VERSION 5.8 ;
BUSBITCHARS "[]" ;
DIVIDERCHAR "/" ;
UNITS
    DATABASE MICRONS 1000 ;
END UNITS

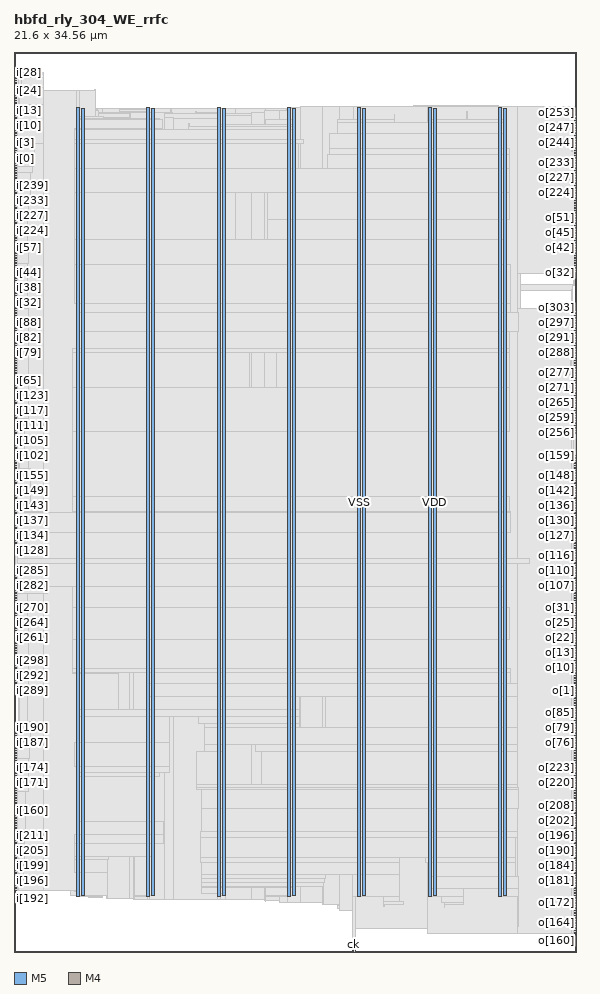
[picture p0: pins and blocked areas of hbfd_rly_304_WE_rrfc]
MACRO hbfd_rly_304_WE_rrfc
  FOREIGN hbfd_rly_304_WE_rrfc 0 0 ;
  CLASS BLOCK ;
  SIZE 21.6 BY 34.56 ;
  PIN ck
    DIRECTION INPUT ;
    USE SIGNAL ;
    PORT
      LAYER M5 ;
        RECT  13.008 0 13.032 0.084 ;
    END
  END ck
  PIN i[0]
    DIRECTION INPUT ;
    USE SIGNAL ;
    PORT
      LAYER M4 ;
        RECT  0 30.768 0.084 30.792 ;
    END
  END i[0]
  PIN i[100]
    DIRECTION INPUT ;
    USE SIGNAL ;
    PORT
      LAYER M4 ;
        RECT  0 18.864 0.084 18.888 ;
    END
  END i[100]
  PIN i[101]
    DIRECTION INPUT ;
    USE SIGNAL ;
    PORT
      LAYER M4 ;
        RECT  0 18.96 0.084 18.984 ;
    END
  END i[101]
  PIN i[102]
    DIRECTION INPUT ;
    USE SIGNAL ;
    PORT
      LAYER M4 ;
        RECT  0 19.056 0.084 19.08 ;
    END
  END i[102]
  PIN i[103]
    DIRECTION INPUT ;
    USE SIGNAL ;
    PORT
      LAYER M4 ;
        RECT  0 19.152 0.084 19.176 ;
    END
  END i[103]
  PIN i[104]
    DIRECTION INPUT ;
    USE SIGNAL ;
    PORT
      LAYER M4 ;
        RECT  0 19.248 0.084 19.272 ;
    END
  END i[104]
  PIN i[105]
    DIRECTION INPUT ;
    USE SIGNAL ;
    PORT
      LAYER M4 ;
        RECT  0 19.344 0.084 19.368 ;
    END
  END i[105]
  PIN i[106]
    DIRECTION INPUT ;
    USE SIGNAL ;
    PORT
      LAYER M4 ;
        RECT  0 19.44 0.084 19.464 ;
    END
  END i[106]
  PIN i[107]
    DIRECTION INPUT ;
    USE SIGNAL ;
    PORT
      LAYER M4 ;
        RECT  0 19.536 0.084 19.56 ;
    END
  END i[107]
  PIN i[108]
    DIRECTION INPUT ;
    USE SIGNAL ;
    PORT
      LAYER M4 ;
        RECT  0 19.632 0.084 19.656 ;
    END
  END i[108]
  PIN i[109]
    DIRECTION INPUT ;
    USE SIGNAL ;
    PORT
      LAYER M4 ;
        RECT  0 19.728 0.084 19.752 ;
    END
  END i[109]
  PIN i[10]
    DIRECTION INPUT ;
    USE SIGNAL ;
    PORT
      LAYER M4 ;
        RECT  0 31.728 0.084 31.752 ;
    END
  END i[10]
  PIN i[110]
    DIRECTION INPUT ;
    USE SIGNAL ;
    PORT
      LAYER M4 ;
        RECT  0 19.824 0.084 19.848 ;
    END
  END i[110]
  PIN i[111]
    DIRECTION INPUT ;
    USE SIGNAL ;
    PORT
      LAYER M4 ;
        RECT  0 19.92 0.084 19.944 ;
    END
  END i[111]
  PIN i[112]
    DIRECTION INPUT ;
    USE SIGNAL ;
    PORT
      LAYER M4 ;
        RECT  0 20.016 0.084 20.04 ;
    END
  END i[112]
  PIN i[113]
    DIRECTION INPUT ;
    USE SIGNAL ;
    PORT
      LAYER M4 ;
        RECT  0 20.112 0.084 20.136 ;
    END
  END i[113]
  PIN i[114]
    DIRECTION INPUT ;
    USE SIGNAL ;
    PORT
      LAYER M4 ;
        RECT  0 20.208 0.084 20.232 ;
    END
  END i[114]
  PIN i[115]
    DIRECTION INPUT ;
    USE SIGNAL ;
    PORT
      LAYER M4 ;
        RECT  0 20.304 0.084 20.328 ;
    END
  END i[115]
  PIN i[116]
    DIRECTION INPUT ;
    USE SIGNAL ;
    PORT
      LAYER M4 ;
        RECT  0 20.4 0.084 20.424 ;
    END
  END i[116]
  PIN i[117]
    DIRECTION INPUT ;
    USE SIGNAL ;
    PORT
      LAYER M4 ;
        RECT  0 20.496 0.084 20.52 ;
    END
  END i[117]
  PIN i[118]
    DIRECTION INPUT ;
    USE SIGNAL ;
    PORT
      LAYER M4 ;
        RECT  0 20.592 0.084 20.616 ;
    END
  END i[118]
  PIN i[119]
    DIRECTION INPUT ;
    USE SIGNAL ;
    PORT
      LAYER M4 ;
        RECT  0 20.688 0.084 20.712 ;
    END
  END i[119]
  PIN i[11]
    DIRECTION INPUT ;
    USE SIGNAL ;
    PORT
      LAYER M4 ;
        RECT  0 31.824 0.084 31.848 ;
    END
  END i[11]
  PIN i[120]
    DIRECTION INPUT ;
    USE SIGNAL ;
    PORT
      LAYER M4 ;
        RECT  0 20.784 0.084 20.808 ;
    END
  END i[120]
  PIN i[121]
    DIRECTION INPUT ;
    USE SIGNAL ;
    PORT
      LAYER M4 ;
        RECT  0 20.88 0.084 20.904 ;
    END
  END i[121]
  PIN i[122]
    DIRECTION INPUT ;
    USE SIGNAL ;
    PORT
      LAYER M4 ;
        RECT  0 20.976 0.084 21 ;
    END
  END i[122]
  PIN i[123]
    DIRECTION INPUT ;
    USE SIGNAL ;
    PORT
      LAYER M4 ;
        RECT  0 21.072 0.084 21.096 ;
    END
  END i[123]
  PIN i[124]
    DIRECTION INPUT ;
    USE SIGNAL ;
    PORT
      LAYER M4 ;
        RECT  0 21.168 0.084 21.192 ;
    END
  END i[124]
  PIN i[125]
    DIRECTION INPUT ;
    USE SIGNAL ;
    PORT
      LAYER M4 ;
        RECT  0 21.264 0.084 21.288 ;
    END
  END i[125]
  PIN i[126]
    DIRECTION INPUT ;
    USE SIGNAL ;
    PORT
      LAYER M4 ;
        RECT  0 21.36 0.084 21.384 ;
    END
  END i[126]
  PIN i[127]
    DIRECTION INPUT ;
    USE SIGNAL ;
    PORT
      LAYER M4 ;
        RECT  0 21.456 0.084 21.48 ;
    END
  END i[127]
  PIN i[128]
    DIRECTION INPUT ;
    USE SIGNAL ;
    PORT
      LAYER M4 ;
        RECT  0 15.408 0.084 15.432 ;
    END
  END i[128]
  PIN i[129]
    DIRECTION INPUT ;
    USE SIGNAL ;
    PORT
      LAYER M4 ;
        RECT  0 15.504 0.084 15.528 ;
    END
  END i[129]
  PIN i[12]
    DIRECTION INPUT ;
    USE SIGNAL ;
    PORT
      LAYER M4 ;
        RECT  0 31.92 0.084 31.944 ;
    END
  END i[12]
  PIN i[130]
    DIRECTION INPUT ;
    USE SIGNAL ;
    PORT
      LAYER M4 ;
        RECT  0 15.6 0.084 15.624 ;
    END
  END i[130]
  PIN i[131]
    DIRECTION INPUT ;
    USE SIGNAL ;
    PORT
      LAYER M4 ;
        RECT  0 15.696 0.084 15.72 ;
    END
  END i[131]
  PIN i[132]
    DIRECTION INPUT ;
    USE SIGNAL ;
    PORT
      LAYER M4 ;
        RECT  0 15.792 0.084 15.816 ;
    END
  END i[132]
  PIN i[133]
    DIRECTION INPUT ;
    USE SIGNAL ;
    PORT
      LAYER M4 ;
        RECT  0 15.888 0.084 15.912 ;
    END
  END i[133]
  PIN i[134]
    DIRECTION INPUT ;
    USE SIGNAL ;
    PORT
      LAYER M4 ;
        RECT  0 15.984 0.084 16.008 ;
    END
  END i[134]
  PIN i[135]
    DIRECTION INPUT ;
    USE SIGNAL ;
    PORT
      LAYER M4 ;
        RECT  0 16.08 0.084 16.104 ;
    END
  END i[135]
  PIN i[136]
    DIRECTION INPUT ;
    USE SIGNAL ;
    PORT
      LAYER M4 ;
        RECT  0 16.176 0.084 16.2 ;
    END
  END i[136]
  PIN i[137]
    DIRECTION INPUT ;
    USE SIGNAL ;
    PORT
      LAYER M4 ;
        RECT  0 16.272 0.084 16.296 ;
    END
  END i[137]
  PIN i[138]
    DIRECTION INPUT ;
    USE SIGNAL ;
    PORT
      LAYER M4 ;
        RECT  0 16.368 0.084 16.392 ;
    END
  END i[138]
  PIN i[139]
    DIRECTION INPUT ;
    USE SIGNAL ;
    PORT
      LAYER M4 ;
        RECT  0 16.464 0.084 16.488 ;
    END
  END i[139]
  PIN i[13]
    DIRECTION INPUT ;
    USE SIGNAL ;
    PORT
      LAYER M4 ;
        RECT  0 32.016 0.084 32.04 ;
    END
  END i[13]
  PIN i[140]
    DIRECTION INPUT ;
    USE SIGNAL ;
    PORT
      LAYER M4 ;
        RECT  0 16.56 0.084 16.584 ;
    END
  END i[140]
  PIN i[141]
    DIRECTION INPUT ;
    USE SIGNAL ;
    PORT
      LAYER M4 ;
        RECT  0 16.656 0.084 16.68 ;
    END
  END i[141]
  PIN i[142]
    DIRECTION INPUT ;
    USE SIGNAL ;
    PORT
      LAYER M4 ;
        RECT  0 16.752 0.084 16.776 ;
    END
  END i[142]
  PIN i[143]
    DIRECTION INPUT ;
    USE SIGNAL ;
    PORT
      LAYER M4 ;
        RECT  0 16.848 0.084 16.872 ;
    END
  END i[143]
  PIN i[144]
    DIRECTION INPUT ;
    USE SIGNAL ;
    PORT
      LAYER M4 ;
        RECT  0 16.944 0.084 16.968 ;
    END
  END i[144]
  PIN i[145]
    DIRECTION INPUT ;
    USE SIGNAL ;
    PORT
      LAYER M4 ;
        RECT  0 17.04 0.084 17.064 ;
    END
  END i[145]
  PIN i[146]
    DIRECTION INPUT ;
    USE SIGNAL ;
    PORT
      LAYER M4 ;
        RECT  0 17.136 0.084 17.16 ;
    END
  END i[146]
  PIN i[147]
    DIRECTION INPUT ;
    USE SIGNAL ;
    PORT
      LAYER M4 ;
        RECT  0 17.232 0.084 17.256 ;
    END
  END i[147]
  PIN i[148]
    DIRECTION INPUT ;
    USE SIGNAL ;
    PORT
      LAYER M4 ;
        RECT  0 17.328 0.084 17.352 ;
    END
  END i[148]
  PIN i[149]
    DIRECTION INPUT ;
    USE SIGNAL ;
    PORT
      LAYER M4 ;
        RECT  0 17.424 0.084 17.448 ;
    END
  END i[149]
  PIN i[14]
    DIRECTION INPUT ;
    USE SIGNAL ;
    PORT
      LAYER M4 ;
        RECT  0 32.112 0.084 32.136 ;
    END
  END i[14]
  PIN i[150]
    DIRECTION INPUT ;
    USE SIGNAL ;
    PORT
      LAYER M4 ;
        RECT  0 17.52 0.084 17.544 ;
    END
  END i[150]
  PIN i[151]
    DIRECTION INPUT ;
    USE SIGNAL ;
    PORT
      LAYER M4 ;
        RECT  0 17.616 0.084 17.64 ;
    END
  END i[151]
  PIN i[152]
    DIRECTION INPUT ;
    USE SIGNAL ;
    PORT
      LAYER M4 ;
        RECT  0 17.712 0.084 17.736 ;
    END
  END i[152]
  PIN i[153]
    DIRECTION INPUT ;
    USE SIGNAL ;
    PORT
      LAYER M4 ;
        RECT  0 17.808 0.084 17.832 ;
    END
  END i[153]
  PIN i[154]
    DIRECTION INPUT ;
    USE SIGNAL ;
    PORT
      LAYER M4 ;
        RECT  0 17.904 0.084 17.928 ;
    END
  END i[154]
  PIN i[155]
    DIRECTION INPUT ;
    USE SIGNAL ;
    PORT
      LAYER M4 ;
        RECT  0 18 0.084 18.024 ;
    END
  END i[155]
  PIN i[156]
    DIRECTION INPUT ;
    USE SIGNAL ;
    PORT
      LAYER M4 ;
        RECT  0 18.096 0.084 18.12 ;
    END
  END i[156]
  PIN i[157]
    DIRECTION INPUT ;
    USE SIGNAL ;
    PORT
      LAYER M4 ;
        RECT  0 18.192 0.084 18.216 ;
    END
  END i[157]
  PIN i[158]
    DIRECTION INPUT ;
    USE SIGNAL ;
    PORT
      LAYER M4 ;
        RECT  0 18.288 0.084 18.312 ;
    END
  END i[158]
  PIN i[159]
    DIRECTION INPUT ;
    USE SIGNAL ;
    PORT
      LAYER M4 ;
        RECT  0 18.384 0.084 18.408 ;
    END
  END i[159]
  PIN i[15]
    DIRECTION INPUT ;
    USE SIGNAL ;
    PORT
      LAYER M4 ;
        RECT  0 32.208 0.084 32.232 ;
    END
  END i[15]
  PIN i[160]
    DIRECTION INPUT ;
    USE SIGNAL ;
    PORT
      LAYER M4 ;
        RECT  0 5.424 0.084 5.448 ;
    END
  END i[160]
  PIN i[161]
    DIRECTION INPUT ;
    USE SIGNAL ;
    PORT
      LAYER M4 ;
        RECT  0 5.52 0.084 5.544 ;
    END
  END i[161]
  PIN i[162]
    DIRECTION INPUT ;
    USE SIGNAL ;
    PORT
      LAYER M4 ;
        RECT  0 5.616 0.084 5.64 ;
    END
  END i[162]
  PIN i[163]
    DIRECTION INPUT ;
    USE SIGNAL ;
    PORT
      LAYER M4 ;
        RECT  0 5.712 0.084 5.736 ;
    END
  END i[163]
  PIN i[164]
    DIRECTION INPUT ;
    USE SIGNAL ;
    PORT
      LAYER M4 ;
        RECT  0 5.808 0.084 5.832 ;
    END
  END i[164]
  PIN i[165]
    DIRECTION INPUT ;
    USE SIGNAL ;
    PORT
      LAYER M4 ;
        RECT  0 5.904 0.084 5.928 ;
    END
  END i[165]
  PIN i[166]
    DIRECTION INPUT ;
    USE SIGNAL ;
    PORT
      LAYER M4 ;
        RECT  0 6 0.084 6.024 ;
    END
  END i[166]
  PIN i[167]
    DIRECTION INPUT ;
    USE SIGNAL ;
    PORT
      LAYER M4 ;
        RECT  0 6.096 0.084 6.12 ;
    END
  END i[167]
  PIN i[168]
    DIRECTION INPUT ;
    USE SIGNAL ;
    PORT
      LAYER M4 ;
        RECT  0 6.192 0.084 6.216 ;
    END
  END i[168]
  PIN i[169]
    DIRECTION INPUT ;
    USE SIGNAL ;
    PORT
      LAYER M4 ;
        RECT  0 6.288 0.084 6.312 ;
    END
  END i[169]
  PIN i[16]
    DIRECTION INPUT ;
    USE SIGNAL ;
    PORT
      LAYER M4 ;
        RECT  0 32.304 0.084 32.328 ;
    END
  END i[16]
  PIN i[170]
    DIRECTION INPUT ;
    USE SIGNAL ;
    PORT
      LAYER M4 ;
        RECT  0 6.384 0.084 6.408 ;
    END
  END i[170]
  PIN i[171]
    DIRECTION INPUT ;
    USE SIGNAL ;
    PORT
      LAYER M4 ;
        RECT  0 6.48 0.084 6.504 ;
    END
  END i[171]
  PIN i[172]
    DIRECTION INPUT ;
    USE SIGNAL ;
    PORT
      LAYER M4 ;
        RECT  0 6.576 0.084 6.6 ;
    END
  END i[172]
  PIN i[173]
    DIRECTION INPUT ;
    USE SIGNAL ;
    PORT
      LAYER M4 ;
        RECT  0 6.672 0.084 6.696 ;
    END
  END i[173]
  PIN i[174]
    DIRECTION INPUT ;
    USE SIGNAL ;
    PORT
      LAYER M4 ;
        RECT  0 6.768 0.084 6.792 ;
    END
  END i[174]
  PIN i[175]
    DIRECTION INPUT ;
    USE SIGNAL ;
    PORT
      LAYER M4 ;
        RECT  0 6.864 0.084 6.888 ;
    END
  END i[175]
  PIN i[176]
    DIRECTION INPUT ;
    USE SIGNAL ;
    PORT
      LAYER M4 ;
        RECT  0 6.96 0.084 6.984 ;
    END
  END i[176]
  PIN i[177]
    DIRECTION INPUT ;
    USE SIGNAL ;
    PORT
      LAYER M4 ;
        RECT  0 7.056 0.084 7.08 ;
    END
  END i[177]
  PIN i[178]
    DIRECTION INPUT ;
    USE SIGNAL ;
    PORT
      LAYER M4 ;
        RECT  0 7.152 0.084 7.176 ;
    END
  END i[178]
  PIN i[179]
    DIRECTION INPUT ;
    USE SIGNAL ;
    PORT
      LAYER M4 ;
        RECT  0 7.248 0.084 7.272 ;
    END
  END i[179]
  PIN i[17]
    DIRECTION INPUT ;
    USE SIGNAL ;
    PORT
      LAYER M4 ;
        RECT  0 32.4 0.084 32.424 ;
    END
  END i[17]
  PIN i[180]
    DIRECTION INPUT ;
    USE SIGNAL ;
    PORT
      LAYER M4 ;
        RECT  0 7.344 0.084 7.368 ;
    END
  END i[180]
  PIN i[181]
    DIRECTION INPUT ;
    USE SIGNAL ;
    PORT
      LAYER M4 ;
        RECT  0 7.44 0.084 7.464 ;
    END
  END i[181]
  PIN i[182]
    DIRECTION INPUT ;
    USE SIGNAL ;
    PORT
      LAYER M4 ;
        RECT  0 7.536 0.084 7.56 ;
    END
  END i[182]
  PIN i[183]
    DIRECTION INPUT ;
    USE SIGNAL ;
    PORT
      LAYER M4 ;
        RECT  0 7.632 0.084 7.656 ;
    END
  END i[183]
  PIN i[184]
    DIRECTION INPUT ;
    USE SIGNAL ;
    PORT
      LAYER M4 ;
        RECT  0 7.728 0.084 7.752 ;
    END
  END i[184]
  PIN i[185]
    DIRECTION INPUT ;
    USE SIGNAL ;
    PORT
      LAYER M4 ;
        RECT  0 7.824 0.084 7.848 ;
    END
  END i[185]
  PIN i[186]
    DIRECTION INPUT ;
    USE SIGNAL ;
    PORT
      LAYER M4 ;
        RECT  0 7.92 0.084 7.944 ;
    END
  END i[186]
  PIN i[187]
    DIRECTION INPUT ;
    USE SIGNAL ;
    PORT
      LAYER M4 ;
        RECT  0 8.016 0.084 8.04 ;
    END
  END i[187]
  PIN i[188]
    DIRECTION INPUT ;
    USE SIGNAL ;
    PORT
      LAYER M4 ;
        RECT  0 8.112 0.084 8.136 ;
    END
  END i[188]
  PIN i[189]
    DIRECTION INPUT ;
    USE SIGNAL ;
    PORT
      LAYER M4 ;
        RECT  0 8.208 0.084 8.232 ;
    END
  END i[189]
  PIN i[18]
    DIRECTION INPUT ;
    USE SIGNAL ;
    PORT
      LAYER M4 ;
        RECT  0 32.496 0.084 32.52 ;
    END
  END i[18]
  PIN i[190]
    DIRECTION INPUT ;
    USE SIGNAL ;
    PORT
      LAYER M4 ;
        RECT  0 8.304 0.084 8.328 ;
    END
  END i[190]
  PIN i[191]
    DIRECTION INPUT ;
    USE SIGNAL ;
    PORT
      LAYER M4 ;
        RECT  0 8.4 0.084 8.424 ;
    END
  END i[191]
  PIN i[192]
    DIRECTION INPUT ;
    USE SIGNAL ;
    PORT
      LAYER M4 ;
        RECT  0 2.352 0.084 2.376 ;
    END
  END i[192]
  PIN i[193]
    DIRECTION INPUT ;
    USE SIGNAL ;
    PORT
      LAYER M4 ;
        RECT  0 2.448 0.084 2.472 ;
    END
  END i[193]
  PIN i[194]
    DIRECTION INPUT ;
    USE SIGNAL ;
    PORT
      LAYER M4 ;
        RECT  0 2.544 0.084 2.568 ;
    END
  END i[194]
  PIN i[195]
    DIRECTION INPUT ;
    USE SIGNAL ;
    PORT
      LAYER M4 ;
        RECT  0 2.64 0.084 2.664 ;
    END
  END i[195]
  PIN i[196]
    DIRECTION INPUT ;
    USE SIGNAL ;
    PORT
      LAYER M4 ;
        RECT  0 2.736 0.084 2.76 ;
    END
  END i[196]
  PIN i[197]
    DIRECTION INPUT ;
    USE SIGNAL ;
    PORT
      LAYER M4 ;
        RECT  0 2.832 0.084 2.856 ;
    END
  END i[197]
  PIN i[198]
    DIRECTION INPUT ;
    USE SIGNAL ;
    PORT
      LAYER M4 ;
        RECT  0 2.928 0.084 2.952 ;
    END
  END i[198]
  PIN i[199]
    DIRECTION INPUT ;
    USE SIGNAL ;
    PORT
      LAYER M4 ;
        RECT  0 3.024 0.084 3.048 ;
    END
  END i[199]
  PIN i[19]
    DIRECTION INPUT ;
    USE SIGNAL ;
    PORT
      LAYER M4 ;
        RECT  0 32.592 0.084 32.616 ;
    END
  END i[19]
  PIN i[1]
    DIRECTION INPUT ;
    USE SIGNAL ;
    PORT
      LAYER M4 ;
        RECT  0 30.864 0.084 30.888 ;
    END
  END i[1]
  PIN i[200]
    DIRECTION INPUT ;
    USE SIGNAL ;
    PORT
      LAYER M4 ;
        RECT  0 3.12 0.084 3.144 ;
    END
  END i[200]
  PIN i[201]
    DIRECTION INPUT ;
    USE SIGNAL ;
    PORT
      LAYER M4 ;
        RECT  0 3.216 0.084 3.24 ;
    END
  END i[201]
  PIN i[202]
    DIRECTION INPUT ;
    USE SIGNAL ;
    PORT
      LAYER M4 ;
        RECT  0 3.312 0.084 3.336 ;
    END
  END i[202]
  PIN i[203]
    DIRECTION INPUT ;
    USE SIGNAL ;
    PORT
      LAYER M4 ;
        RECT  0 3.408 0.084 3.432 ;
    END
  END i[203]
  PIN i[204]
    DIRECTION INPUT ;
    USE SIGNAL ;
    PORT
      LAYER M4 ;
        RECT  0 3.504 0.084 3.528 ;
    END
  END i[204]
  PIN i[205]
    DIRECTION INPUT ;
    USE SIGNAL ;
    PORT
      LAYER M4 ;
        RECT  0 3.6 0.084 3.624 ;
    END
  END i[205]
  PIN i[206]
    DIRECTION INPUT ;
    USE SIGNAL ;
    PORT
      LAYER M4 ;
        RECT  0 3.696 0.084 3.72 ;
    END
  END i[206]
  PIN i[207]
    DIRECTION INPUT ;
    USE SIGNAL ;
    PORT
      LAYER M4 ;
        RECT  0 3.792 0.084 3.816 ;
    END
  END i[207]
  PIN i[208]
    DIRECTION INPUT ;
    USE SIGNAL ;
    PORT
      LAYER M4 ;
        RECT  0 3.888 0.084 3.912 ;
    END
  END i[208]
  PIN i[209]
    DIRECTION INPUT ;
    USE SIGNAL ;
    PORT
      LAYER M4 ;
        RECT  0 3.984 0.084 4.008 ;
    END
  END i[209]
  PIN i[20]
    DIRECTION INPUT ;
    USE SIGNAL ;
    PORT
      LAYER M4 ;
        RECT  0 32.688 0.084 32.712 ;
    END
  END i[20]
  PIN i[210]
    DIRECTION INPUT ;
    USE SIGNAL ;
    PORT
      LAYER M4 ;
        RECT  0 4.08 0.084 4.104 ;
    END
  END i[210]
  PIN i[211]
    DIRECTION INPUT ;
    USE SIGNAL ;
    PORT
      LAYER M4 ;
        RECT  0 4.176 0.084 4.2 ;
    END
  END i[211]
  PIN i[212]
    DIRECTION INPUT ;
    USE SIGNAL ;
    PORT
      LAYER M4 ;
        RECT  0 4.272 0.084 4.296 ;
    END
  END i[212]
  PIN i[213]
    DIRECTION INPUT ;
    USE SIGNAL ;
    PORT
      LAYER M4 ;
        RECT  0 4.368 0.084 4.392 ;
    END
  END i[213]
  PIN i[214]
    DIRECTION INPUT ;
    USE SIGNAL ;
    PORT
      LAYER M4 ;
        RECT  0 4.464 0.084 4.488 ;
    END
  END i[214]
  PIN i[215]
    DIRECTION INPUT ;
    USE SIGNAL ;
    PORT
      LAYER M4 ;
        RECT  0 4.56 0.084 4.584 ;
    END
  END i[215]
  PIN i[216]
    DIRECTION INPUT ;
    USE SIGNAL ;
    PORT
      LAYER M4 ;
        RECT  0 4.656 0.084 4.68 ;
    END
  END i[216]
  PIN i[217]
    DIRECTION INPUT ;
    USE SIGNAL ;
    PORT
      LAYER M4 ;
        RECT  0 4.752 0.084 4.776 ;
    END
  END i[217]
  PIN i[218]
    DIRECTION INPUT ;
    USE SIGNAL ;
    PORT
      LAYER M4 ;
        RECT  0 4.848 0.084 4.872 ;
    END
  END i[218]
  PIN i[219]
    DIRECTION INPUT ;
    USE SIGNAL ;
    PORT
      LAYER M4 ;
        RECT  0 4.944 0.084 4.968 ;
    END
  END i[219]
  PIN i[21]
    DIRECTION INPUT ;
    USE SIGNAL ;
    PORT
      LAYER M4 ;
        RECT  0 32.784 0.084 32.808 ;
    END
  END i[21]
  PIN i[220]
    DIRECTION INPUT ;
    USE SIGNAL ;
    PORT
      LAYER M4 ;
        RECT  0 5.04 0.084 5.064 ;
    END
  END i[220]
  PIN i[221]
    DIRECTION INPUT ;
    USE SIGNAL ;
    PORT
      LAYER M4 ;
        RECT  0 5.136 0.084 5.16 ;
    END
  END i[221]
  PIN i[222]
    DIRECTION INPUT ;
    USE SIGNAL ;
    PORT
      LAYER M4 ;
        RECT  0 5.232 0.084 5.256 ;
    END
  END i[222]
  PIN i[223]
    DIRECTION INPUT ;
    USE SIGNAL ;
    PORT
      LAYER M4 ;
        RECT  0 5.328 0.084 5.352 ;
    END
  END i[223]
  PIN i[224]
    DIRECTION INPUT ;
    USE SIGNAL ;
    PORT
      LAYER M4 ;
        RECT  0 27.696 0.084 27.72 ;
    END
  END i[224]
  PIN i[225]
    DIRECTION INPUT ;
    USE SIGNAL ;
    PORT
      LAYER M4 ;
        RECT  0 27.792 0.084 27.816 ;
    END
  END i[225]
  PIN i[226]
    DIRECTION INPUT ;
    USE SIGNAL ;
    PORT
      LAYER M4 ;
        RECT  0 27.888 0.084 27.912 ;
    END
  END i[226]
  PIN i[227]
    DIRECTION INPUT ;
    USE SIGNAL ;
    PORT
      LAYER M4 ;
        RECT  0 27.984 0.084 28.008 ;
    END
  END i[227]
  PIN i[228]
    DIRECTION INPUT ;
    USE SIGNAL ;
    PORT
      LAYER M4 ;
        RECT  0 28.08 0.084 28.104 ;
    END
  END i[228]
  PIN i[229]
    DIRECTION INPUT ;
    USE SIGNAL ;
    PORT
      LAYER M4 ;
        RECT  0 28.176 0.084 28.2 ;
    END
  END i[229]
  PIN i[22]
    DIRECTION INPUT ;
    USE SIGNAL ;
    PORT
      LAYER M4 ;
        RECT  0 32.88 0.084 32.904 ;
    END
  END i[22]
  PIN i[230]
    DIRECTION INPUT ;
    USE SIGNAL ;
    PORT
      LAYER M4 ;
        RECT  0 28.272 0.084 28.296 ;
    END
  END i[230]
  PIN i[231]
    DIRECTION INPUT ;
    USE SIGNAL ;
    PORT
      LAYER M4 ;
        RECT  0 28.368 0.084 28.392 ;
    END
  END i[231]
  PIN i[232]
    DIRECTION INPUT ;
    USE SIGNAL ;
    PORT
      LAYER M4 ;
        RECT  0 28.464 0.084 28.488 ;
    END
  END i[232]
  PIN i[233]
    DIRECTION INPUT ;
    USE SIGNAL ;
    PORT
      LAYER M4 ;
        RECT  0 28.56 0.084 28.584 ;
    END
  END i[233]
  PIN i[234]
    DIRECTION INPUT ;
    USE SIGNAL ;
    PORT
      LAYER M4 ;
        RECT  0 28.656 0.084 28.68 ;
    END
  END i[234]
  PIN i[235]
    DIRECTION INPUT ;
    USE SIGNAL ;
    PORT
      LAYER M4 ;
        RECT  0 28.752 0.084 28.776 ;
    END
  END i[235]
  PIN i[236]
    DIRECTION INPUT ;
    USE SIGNAL ;
    PORT
      LAYER M4 ;
        RECT  0 28.848 0.084 28.872 ;
    END
  END i[236]
  PIN i[237]
    DIRECTION INPUT ;
    USE SIGNAL ;
    PORT
      LAYER M4 ;
        RECT  0 28.944 0.084 28.968 ;
    END
  END i[237]
  PIN i[238]
    DIRECTION INPUT ;
    USE SIGNAL ;
    PORT
      LAYER M4 ;
        RECT  0 29.04 0.084 29.064 ;
    END
  END i[238]
  PIN i[239]
    DIRECTION INPUT ;
    USE SIGNAL ;
    PORT
      LAYER M4 ;
        RECT  0 29.136 0.084 29.16 ;
    END
  END i[239]
  PIN i[23]
    DIRECTION INPUT ;
    USE SIGNAL ;
    PORT
      LAYER M4 ;
        RECT  0 32.976 0.084 33 ;
    END
  END i[23]
  PIN i[240]
    DIRECTION INPUT ;
    USE SIGNAL ;
    PORT
      LAYER M4 ;
        RECT  0 29.232 0.084 29.256 ;
    END
  END i[240]
  PIN i[241]
    DIRECTION INPUT ;
    USE SIGNAL ;
    PORT
      LAYER M4 ;
        RECT  0 29.328 0.084 29.352 ;
    END
  END i[241]
  PIN i[242]
    DIRECTION INPUT ;
    USE SIGNAL ;
    PORT
      LAYER M4 ;
        RECT  0 29.424 0.084 29.448 ;
    END
  END i[242]
  PIN i[243]
    DIRECTION INPUT ;
    USE SIGNAL ;
    PORT
      LAYER M4 ;
        RECT  0 29.52 0.084 29.544 ;
    END
  END i[243]
  PIN i[244]
    DIRECTION INPUT ;
    USE SIGNAL ;
    PORT
      LAYER M4 ;
        RECT  0 29.616 0.084 29.64 ;
    END
  END i[244]
  PIN i[245]
    DIRECTION INPUT ;
    USE SIGNAL ;
    PORT
      LAYER M4 ;
        RECT  0 29.712 0.084 29.736 ;
    END
  END i[245]
  PIN i[246]
    DIRECTION INPUT ;
    USE SIGNAL ;
    PORT
      LAYER M4 ;
        RECT  0 29.808 0.084 29.832 ;
    END
  END i[246]
  PIN i[247]
    DIRECTION INPUT ;
    USE SIGNAL ;
    PORT
      LAYER M4 ;
        RECT  0 29.904 0.084 29.928 ;
    END
  END i[247]
  PIN i[248]
    DIRECTION INPUT ;
    USE SIGNAL ;
    PORT
      LAYER M4 ;
        RECT  0 30 0.084 30.024 ;
    END
  END i[248]
  PIN i[249]
    DIRECTION INPUT ;
    USE SIGNAL ;
    PORT
      LAYER M4 ;
        RECT  0 30.096 0.084 30.12 ;
    END
  END i[249]
  PIN i[24]
    DIRECTION INPUT ;
    USE SIGNAL ;
    PORT
      LAYER M4 ;
        RECT  0 33.072 0.084 33.096 ;
    END
  END i[24]
  PIN i[250]
    DIRECTION INPUT ;
    USE SIGNAL ;
    PORT
      LAYER M4 ;
        RECT  0 30.192 0.084 30.216 ;
    END
  END i[250]
  PIN i[251]
    DIRECTION INPUT ;
    USE SIGNAL ;
    PORT
      LAYER M4 ;
        RECT  0 30.288 0.084 30.312 ;
    END
  END i[251]
  PIN i[252]
    DIRECTION INPUT ;
    USE SIGNAL ;
    PORT
      LAYER M4 ;
        RECT  0 30.384 0.084 30.408 ;
    END
  END i[252]
  PIN i[253]
    DIRECTION INPUT ;
    USE SIGNAL ;
    PORT
      LAYER M4 ;
        RECT  0 30.48 0.084 30.504 ;
    END
  END i[253]
  PIN i[254]
    DIRECTION INPUT ;
    USE SIGNAL ;
    PORT
      LAYER M4 ;
        RECT  0 30.576 0.084 30.6 ;
    END
  END i[254]
  PIN i[255]
    DIRECTION INPUT ;
    USE SIGNAL ;
    PORT
      LAYER M4 ;
        RECT  0 30.672 0.084 30.696 ;
    END
  END i[255]
  PIN i[256]
    DIRECTION INPUT ;
    USE SIGNAL ;
    PORT
      LAYER M4 ;
        RECT  0 11.568 0.084 11.592 ;
    END
  END i[256]
  PIN i[257]
    DIRECTION INPUT ;
    USE SIGNAL ;
    PORT
      LAYER M4 ;
        RECT  0 11.664 0.084 11.688 ;
    END
  END i[257]
  PIN i[258]
    DIRECTION INPUT ;
    USE SIGNAL ;
    PORT
      LAYER M4 ;
        RECT  0 11.76 0.084 11.784 ;
    END
  END i[258]
  PIN i[259]
    DIRECTION INPUT ;
    USE SIGNAL ;
    PORT
      LAYER M4 ;
        RECT  0 11.856 0.084 11.88 ;
    END
  END i[259]
  PIN i[25]
    DIRECTION INPUT ;
    USE SIGNAL ;
    PORT
      LAYER M4 ;
        RECT  0 33.168 0.084 33.192 ;
    END
  END i[25]
  PIN i[260]
    DIRECTION INPUT ;
    USE SIGNAL ;
    PORT
      LAYER M4 ;
        RECT  0 11.952 0.084 11.976 ;
    END
  END i[260]
  PIN i[261]
    DIRECTION INPUT ;
    USE SIGNAL ;
    PORT
      LAYER M4 ;
        RECT  0 12.048 0.084 12.072 ;
    END
  END i[261]
  PIN i[262]
    DIRECTION INPUT ;
    USE SIGNAL ;
    PORT
      LAYER M4 ;
        RECT  0 12.144 0.084 12.168 ;
    END
  END i[262]
  PIN i[263]
    DIRECTION INPUT ;
    USE SIGNAL ;
    PORT
      LAYER M4 ;
        RECT  0 12.24 0.084 12.264 ;
    END
  END i[263]
  PIN i[264]
    DIRECTION INPUT ;
    USE SIGNAL ;
    PORT
      LAYER M4 ;
        RECT  0 12.336 0.084 12.36 ;
    END
  END i[264]
  PIN i[265]
    DIRECTION INPUT ;
    USE SIGNAL ;
    PORT
      LAYER M4 ;
        RECT  0 12.432 0.084 12.456 ;
    END
  END i[265]
  PIN i[266]
    DIRECTION INPUT ;
    USE SIGNAL ;
    PORT
      LAYER M4 ;
        RECT  0 12.528 0.084 12.552 ;
    END
  END i[266]
  PIN i[267]
    DIRECTION INPUT ;
    USE SIGNAL ;
    PORT
      LAYER M4 ;
        RECT  0 12.624 0.084 12.648 ;
    END
  END i[267]
  PIN i[268]
    DIRECTION INPUT ;
    USE SIGNAL ;
    PORT
      LAYER M4 ;
        RECT  0 12.72 0.084 12.744 ;
    END
  END i[268]
  PIN i[269]
    DIRECTION INPUT ;
    USE SIGNAL ;
    PORT
      LAYER M4 ;
        RECT  0 12.816 0.084 12.84 ;
    END
  END i[269]
  PIN i[26]
    DIRECTION INPUT ;
    USE SIGNAL ;
    PORT
      LAYER M4 ;
        RECT  0 33.264 0.084 33.288 ;
    END
  END i[26]
  PIN i[270]
    DIRECTION INPUT ;
    USE SIGNAL ;
    PORT
      LAYER M4 ;
        RECT  0 12.912 0.084 12.936 ;
    END
  END i[270]
  PIN i[271]
    DIRECTION INPUT ;
    USE SIGNAL ;
    PORT
      LAYER M4 ;
        RECT  0 13.008 0.084 13.032 ;
    END
  END i[271]
  PIN i[272]
    DIRECTION INPUT ;
    USE SIGNAL ;
    PORT
      LAYER M4 ;
        RECT  0 13.104 0.084 13.128 ;
    END
  END i[272]
  PIN i[273]
    DIRECTION INPUT ;
    USE SIGNAL ;
    PORT
      LAYER M4 ;
        RECT  0 13.2 0.084 13.224 ;
    END
  END i[273]
  PIN i[274]
    DIRECTION INPUT ;
    USE SIGNAL ;
    PORT
      LAYER M4 ;
        RECT  0 13.296 0.084 13.32 ;
    END
  END i[274]
  PIN i[275]
    DIRECTION INPUT ;
    USE SIGNAL ;
    PORT
      LAYER M4 ;
        RECT  0 13.392 0.084 13.416 ;
    END
  END i[275]
  PIN i[276]
    DIRECTION INPUT ;
    USE SIGNAL ;
    PORT
      LAYER M4 ;
        RECT  0 13.488 0.084 13.512 ;
    END
  END i[276]
  PIN i[277]
    DIRECTION INPUT ;
    USE SIGNAL ;
    PORT
      LAYER M4 ;
        RECT  0 13.584 0.084 13.608 ;
    END
  END i[277]
  PIN i[278]
    DIRECTION INPUT ;
    USE SIGNAL ;
    PORT
      LAYER M4 ;
        RECT  0 13.68 0.084 13.704 ;
    END
  END i[278]
  PIN i[279]
    DIRECTION INPUT ;
    USE SIGNAL ;
    PORT
      LAYER M4 ;
        RECT  0 13.776 0.084 13.8 ;
    END
  END i[279]
  PIN i[27]
    DIRECTION INPUT ;
    USE SIGNAL ;
    PORT
      LAYER M4 ;
        RECT  0 33.36 0.084 33.384 ;
    END
  END i[27]
  PIN i[280]
    DIRECTION INPUT ;
    USE SIGNAL ;
    PORT
      LAYER M4 ;
        RECT  0 13.872 0.084 13.896 ;
    END
  END i[280]
  PIN i[281]
    DIRECTION INPUT ;
    USE SIGNAL ;
    PORT
      LAYER M4 ;
        RECT  0 13.968 0.084 13.992 ;
    END
  END i[281]
  PIN i[282]
    DIRECTION INPUT ;
    USE SIGNAL ;
    PORT
      LAYER M4 ;
        RECT  0 14.064 0.084 14.088 ;
    END
  END i[282]
  PIN i[283]
    DIRECTION INPUT ;
    USE SIGNAL ;
    PORT
      LAYER M4 ;
        RECT  0 14.16 0.084 14.184 ;
    END
  END i[283]
  PIN i[284]
    DIRECTION INPUT ;
    USE SIGNAL ;
    PORT
      LAYER M4 ;
        RECT  0 14.256 0.084 14.28 ;
    END
  END i[284]
  PIN i[285]
    DIRECTION INPUT ;
    USE SIGNAL ;
    PORT
      LAYER M4 ;
        RECT  0 14.352 0.084 14.376 ;
    END
  END i[285]
  PIN i[286]
    DIRECTION INPUT ;
    USE SIGNAL ;
    PORT
      LAYER M4 ;
        RECT  0 14.448 0.084 14.472 ;
    END
  END i[286]
  PIN i[287]
    DIRECTION INPUT ;
    USE SIGNAL ;
    PORT
      LAYER M4 ;
        RECT  0 14.544 0.084 14.568 ;
    END
  END i[287]
  PIN i[288]
    DIRECTION INPUT ;
    USE SIGNAL ;
    PORT
      LAYER M4 ;
        RECT  0 9.936 0.084 9.96 ;
    END
  END i[288]
  PIN i[289]
    DIRECTION INPUT ;
    USE SIGNAL ;
    PORT
      LAYER M4 ;
        RECT  0 10.032 0.084 10.056 ;
    END
  END i[289]
  PIN i[28]
    DIRECTION INPUT ;
    USE SIGNAL ;
    PORT
      LAYER M4 ;
        RECT  0 33.456 0.084 33.48 ;
    END
  END i[28]
  PIN i[290]
    DIRECTION INPUT ;
    USE SIGNAL ;
    PORT
      LAYER M4 ;
        RECT  0 10.128 0.084 10.152 ;
    END
  END i[290]
  PIN i[291]
    DIRECTION INPUT ;
    USE SIGNAL ;
    PORT
      LAYER M4 ;
        RECT  0 10.224 0.084 10.248 ;
    END
  END i[291]
  PIN i[292]
    DIRECTION INPUT ;
    USE SIGNAL ;
    PORT
      LAYER M4 ;
        RECT  0 10.32 0.084 10.344 ;
    END
  END i[292]
  PIN i[293]
    DIRECTION INPUT ;
    USE SIGNAL ;
    PORT
      LAYER M4 ;
        RECT  0 10.416 0.084 10.44 ;
    END
  END i[293]
  PIN i[294]
    DIRECTION INPUT ;
    USE SIGNAL ;
    PORT
      LAYER M4 ;
        RECT  0 10.512 0.084 10.536 ;
    END
  END i[294]
  PIN i[295]
    DIRECTION INPUT ;
    USE SIGNAL ;
    PORT
      LAYER M4 ;
        RECT  0 10.608 0.084 10.632 ;
    END
  END i[295]
  PIN i[296]
    DIRECTION INPUT ;
    USE SIGNAL ;
    PORT
      LAYER M4 ;
        RECT  0 10.704 0.084 10.728 ;
    END
  END i[296]
  PIN i[297]
    DIRECTION INPUT ;
    USE SIGNAL ;
    PORT
      LAYER M4 ;
        RECT  0 10.8 0.084 10.824 ;
    END
  END i[297]
  PIN i[298]
    DIRECTION INPUT ;
    USE SIGNAL ;
    PORT
      LAYER M4 ;
        RECT  0 10.896 0.084 10.92 ;
    END
  END i[298]
  PIN i[299]
    DIRECTION INPUT ;
    USE SIGNAL ;
    PORT
      LAYER M4 ;
        RECT  0 10.992 0.084 11.016 ;
    END
  END i[299]
  PIN i[29]
    DIRECTION INPUT ;
    USE SIGNAL ;
    PORT
      LAYER M4 ;
        RECT  0 33.552 0.084 33.576 ;
    END
  END i[29]
  PIN i[2]
    DIRECTION INPUT ;
    USE SIGNAL ;
    PORT
      LAYER M4 ;
        RECT  0 30.96 0.084 30.984 ;
    END
  END i[2]
  PIN i[300]
    DIRECTION INPUT ;
    USE SIGNAL ;
    PORT
      LAYER M4 ;
        RECT  0 11.088 0.084 11.112 ;
    END
  END i[300]
  PIN i[301]
    DIRECTION INPUT ;
    USE SIGNAL ;
    PORT
      LAYER M4 ;
        RECT  0 11.184 0.084 11.208 ;
    END
  END i[301]
  PIN i[302]
    DIRECTION INPUT ;
    USE SIGNAL ;
    PORT
      LAYER M4 ;
        RECT  0 11.28 0.084 11.304 ;
    END
  END i[302]
  PIN i[303]
    DIRECTION INPUT ;
    USE SIGNAL ;
    PORT
      LAYER M4 ;
        RECT  0 11.376 0.084 11.4 ;
    END
  END i[303]
  PIN i[30]
    DIRECTION INPUT ;
    USE SIGNAL ;
    PORT
      LAYER M4 ;
        RECT  0 33.648 0.084 33.672 ;
    END
  END i[30]
  PIN i[31]
    DIRECTION INPUT ;
    USE SIGNAL ;
    PORT
      LAYER M4 ;
        RECT  0 33.744 0.084 33.768 ;
    END
  END i[31]
  PIN i[32]
    DIRECTION INPUT ;
    USE SIGNAL ;
    PORT
      LAYER M4 ;
        RECT  0 24.624 0.084 24.648 ;
    END
  END i[32]
  PIN i[33]
    DIRECTION INPUT ;
    USE SIGNAL ;
    PORT
      LAYER M4 ;
        RECT  0 24.72 0.084 24.744 ;
    END
  END i[33]
  PIN i[34]
    DIRECTION INPUT ;
    USE SIGNAL ;
    PORT
      LAYER M4 ;
        RECT  0 24.816 0.084 24.84 ;
    END
  END i[34]
  PIN i[35]
    DIRECTION INPUT ;
    USE SIGNAL ;
    PORT
      LAYER M4 ;
        RECT  0 24.912 0.084 24.936 ;
    END
  END i[35]
  PIN i[36]
    DIRECTION INPUT ;
    USE SIGNAL ;
    PORT
      LAYER M4 ;
        RECT  0 25.008 0.084 25.032 ;
    END
  END i[36]
  PIN i[37]
    DIRECTION INPUT ;
    USE SIGNAL ;
    PORT
      LAYER M4 ;
        RECT  0 25.104 0.084 25.128 ;
    END
  END i[37]
  PIN i[38]
    DIRECTION INPUT ;
    USE SIGNAL ;
    PORT
      LAYER M4 ;
        RECT  0 25.2 0.084 25.224 ;
    END
  END i[38]
  PIN i[39]
    DIRECTION INPUT ;
    USE SIGNAL ;
    PORT
      LAYER M4 ;
        RECT  0 25.296 0.084 25.32 ;
    END
  END i[39]
  PIN i[3]
    DIRECTION INPUT ;
    USE SIGNAL ;
    PORT
      LAYER M4 ;
        RECT  0 31.056 0.084 31.08 ;
    END
  END i[3]
  PIN i[40]
    DIRECTION INPUT ;
    USE SIGNAL ;
    PORT
      LAYER M4 ;
        RECT  0 25.392 0.084 25.416 ;
    END
  END i[40]
  PIN i[41]
    DIRECTION INPUT ;
    USE SIGNAL ;
    PORT
      LAYER M4 ;
        RECT  0 25.488 0.084 25.512 ;
    END
  END i[41]
  PIN i[42]
    DIRECTION INPUT ;
    USE SIGNAL ;
    PORT
      LAYER M4 ;
        RECT  0 25.584 0.084 25.608 ;
    END
  END i[42]
  PIN i[43]
    DIRECTION INPUT ;
    USE SIGNAL ;
    PORT
      LAYER M4 ;
        RECT  0 25.68 0.084 25.704 ;
    END
  END i[43]
  PIN i[44]
    DIRECTION INPUT ;
    USE SIGNAL ;
    PORT
      LAYER M4 ;
        RECT  0 25.776 0.084 25.8 ;
    END
  END i[44]
  PIN i[45]
    DIRECTION INPUT ;
    USE SIGNAL ;
    PORT
      LAYER M4 ;
        RECT  0 25.872 0.084 25.896 ;
    END
  END i[45]
  PIN i[46]
    DIRECTION INPUT ;
    USE SIGNAL ;
    PORT
      LAYER M4 ;
        RECT  0 25.968 0.084 25.992 ;
    END
  END i[46]
  PIN i[47]
    DIRECTION INPUT ;
    USE SIGNAL ;
    PORT
      LAYER M4 ;
        RECT  0 26.064 0.084 26.088 ;
    END
  END i[47]
  PIN i[48]
    DIRECTION INPUT ;
    USE SIGNAL ;
    PORT
      LAYER M4 ;
        RECT  0 26.16 0.084 26.184 ;
    END
  END i[48]
  PIN i[49]
    DIRECTION INPUT ;
    USE SIGNAL ;
    PORT
      LAYER M4 ;
        RECT  0 26.256 0.084 26.28 ;
    END
  END i[49]
  PIN i[4]
    DIRECTION INPUT ;
    USE SIGNAL ;
    PORT
      LAYER M4 ;
        RECT  0 31.152 0.084 31.176 ;
    END
  END i[4]
  PIN i[50]
    DIRECTION INPUT ;
    USE SIGNAL ;
    PORT
      LAYER M4 ;
        RECT  0 26.352 0.084 26.376 ;
    END
  END i[50]
  PIN i[51]
    DIRECTION INPUT ;
    USE SIGNAL ;
    PORT
      LAYER M4 ;
        RECT  0 26.448 0.084 26.472 ;
    END
  END i[51]
  PIN i[52]
    DIRECTION INPUT ;
    USE SIGNAL ;
    PORT
      LAYER M4 ;
        RECT  0 26.544 0.084 26.568 ;
    END
  END i[52]
  PIN i[53]
    DIRECTION INPUT ;
    USE SIGNAL ;
    PORT
      LAYER M4 ;
        RECT  0 26.64 0.084 26.664 ;
    END
  END i[53]
  PIN i[54]
    DIRECTION INPUT ;
    USE SIGNAL ;
    PORT
      LAYER M4 ;
        RECT  0 26.736 0.084 26.76 ;
    END
  END i[54]
  PIN i[55]
    DIRECTION INPUT ;
    USE SIGNAL ;
    PORT
      LAYER M4 ;
        RECT  0 26.832 0.084 26.856 ;
    END
  END i[55]
  PIN i[56]
    DIRECTION INPUT ;
    USE SIGNAL ;
    PORT
      LAYER M4 ;
        RECT  0 26.928 0.084 26.952 ;
    END
  END i[56]
  PIN i[57]
    DIRECTION INPUT ;
    USE SIGNAL ;
    PORT
      LAYER M4 ;
        RECT  0 27.024 0.084 27.048 ;
    END
  END i[57]
  PIN i[58]
    DIRECTION INPUT ;
    USE SIGNAL ;
    PORT
      LAYER M4 ;
        RECT  0 27.12 0.084 27.144 ;
    END
  END i[58]
  PIN i[59]
    DIRECTION INPUT ;
    USE SIGNAL ;
    PORT
      LAYER M4 ;
        RECT  0 27.216 0.084 27.24 ;
    END
  END i[59]
  PIN i[5]
    DIRECTION INPUT ;
    USE SIGNAL ;
    PORT
      LAYER M4 ;
        RECT  0 31.248 0.084 31.272 ;
    END
  END i[5]
  PIN i[60]
    DIRECTION INPUT ;
    USE SIGNAL ;
    PORT
      LAYER M4 ;
        RECT  0 27.312 0.084 27.336 ;
    END
  END i[60]
  PIN i[61]
    DIRECTION INPUT ;
    USE SIGNAL ;
    PORT
      LAYER M4 ;
        RECT  0 27.408 0.084 27.432 ;
    END
  END i[61]
  PIN i[62]
    DIRECTION INPUT ;
    USE SIGNAL ;
    PORT
      LAYER M4 ;
        RECT  0 27.504 0.084 27.528 ;
    END
  END i[62]
  PIN i[63]
    DIRECTION INPUT ;
    USE SIGNAL ;
    PORT
      LAYER M4 ;
        RECT  0 27.6 0.084 27.624 ;
    END
  END i[63]
  PIN i[64]
    DIRECTION INPUT ;
    USE SIGNAL ;
    PORT
      LAYER M4 ;
        RECT  0 21.552 0.084 21.576 ;
    END
  END i[64]
  PIN i[65]
    DIRECTION INPUT ;
    USE SIGNAL ;
    PORT
      LAYER M4 ;
        RECT  0 21.648 0.084 21.672 ;
    END
  END i[65]
  PIN i[66]
    DIRECTION INPUT ;
    USE SIGNAL ;
    PORT
      LAYER M4 ;
        RECT  0 21.744 0.084 21.768 ;
    END
  END i[66]
  PIN i[67]
    DIRECTION INPUT ;
    USE SIGNAL ;
    PORT
      LAYER M4 ;
        RECT  0 21.84 0.084 21.864 ;
    END
  END i[67]
  PIN i[68]
    DIRECTION INPUT ;
    USE SIGNAL ;
    PORT
      LAYER M4 ;
        RECT  0 21.936 0.084 21.96 ;
    END
  END i[68]
  PIN i[69]
    DIRECTION INPUT ;
    USE SIGNAL ;
    PORT
      LAYER M4 ;
        RECT  0 22.032 0.084 22.056 ;
    END
  END i[69]
  PIN i[6]
    DIRECTION INPUT ;
    USE SIGNAL ;
    PORT
      LAYER M4 ;
        RECT  0 31.344 0.084 31.368 ;
    END
  END i[6]
  PIN i[70]
    DIRECTION INPUT ;
    USE SIGNAL ;
    PORT
      LAYER M4 ;
        RECT  0 22.128 0.084 22.152 ;
    END
  END i[70]
  PIN i[71]
    DIRECTION INPUT ;
    USE SIGNAL ;
    PORT
      LAYER M4 ;
        RECT  0 22.224 0.084 22.248 ;
    END
  END i[71]
  PIN i[72]
    DIRECTION INPUT ;
    USE SIGNAL ;
    PORT
      LAYER M4 ;
        RECT  0 22.32 0.084 22.344 ;
    END
  END i[72]
  PIN i[73]
    DIRECTION INPUT ;
    USE SIGNAL ;
    PORT
      LAYER M4 ;
        RECT  0 22.416 0.084 22.44 ;
    END
  END i[73]
  PIN i[74]
    DIRECTION INPUT ;
    USE SIGNAL ;
    PORT
      LAYER M4 ;
        RECT  0 22.512 0.084 22.536 ;
    END
  END i[74]
  PIN i[75]
    DIRECTION INPUT ;
    USE SIGNAL ;
    PORT
      LAYER M4 ;
        RECT  0 22.608 0.084 22.632 ;
    END
  END i[75]
  PIN i[76]
    DIRECTION INPUT ;
    USE SIGNAL ;
    PORT
      LAYER M4 ;
        RECT  0 22.704 0.084 22.728 ;
    END
  END i[76]
  PIN i[77]
    DIRECTION INPUT ;
    USE SIGNAL ;
    PORT
      LAYER M4 ;
        RECT  0 22.8 0.084 22.824 ;
    END
  END i[77]
  PIN i[78]
    DIRECTION INPUT ;
    USE SIGNAL ;
    PORT
      LAYER M4 ;
        RECT  0 22.896 0.084 22.92 ;
    END
  END i[78]
  PIN i[79]
    DIRECTION INPUT ;
    USE SIGNAL ;
    PORT
      LAYER M4 ;
        RECT  0 22.992 0.084 23.016 ;
    END
  END i[79]
  PIN i[7]
    DIRECTION INPUT ;
    USE SIGNAL ;
    PORT
      LAYER M4 ;
        RECT  0 31.44 0.084 31.464 ;
    END
  END i[7]
  PIN i[80]
    DIRECTION INPUT ;
    USE SIGNAL ;
    PORT
      LAYER M4 ;
        RECT  0 23.088 0.084 23.112 ;
    END
  END i[80]
  PIN i[81]
    DIRECTION INPUT ;
    USE SIGNAL ;
    PORT
      LAYER M4 ;
        RECT  0 23.184 0.084 23.208 ;
    END
  END i[81]
  PIN i[82]
    DIRECTION INPUT ;
    USE SIGNAL ;
    PORT
      LAYER M4 ;
        RECT  0 23.28 0.084 23.304 ;
    END
  END i[82]
  PIN i[83]
    DIRECTION INPUT ;
    USE SIGNAL ;
    PORT
      LAYER M4 ;
        RECT  0 23.376 0.084 23.4 ;
    END
  END i[83]
  PIN i[84]
    DIRECTION INPUT ;
    USE SIGNAL ;
    PORT
      LAYER M4 ;
        RECT  0 23.472 0.084 23.496 ;
    END
  END i[84]
  PIN i[85]
    DIRECTION INPUT ;
    USE SIGNAL ;
    PORT
      LAYER M4 ;
        RECT  0 23.568 0.084 23.592 ;
    END
  END i[85]
  PIN i[86]
    DIRECTION INPUT ;
    USE SIGNAL ;
    PORT
      LAYER M4 ;
        RECT  0 23.664 0.084 23.688 ;
    END
  END i[86]
  PIN i[87]
    DIRECTION INPUT ;
    USE SIGNAL ;
    PORT
      LAYER M4 ;
        RECT  0 23.76 0.084 23.784 ;
    END
  END i[87]
  PIN i[88]
    DIRECTION INPUT ;
    USE SIGNAL ;
    PORT
      LAYER M4 ;
        RECT  0 23.856 0.084 23.88 ;
    END
  END i[88]
  PIN i[89]
    DIRECTION INPUT ;
    USE SIGNAL ;
    PORT
      LAYER M4 ;
        RECT  0 23.952 0.084 23.976 ;
    END
  END i[89]
  PIN i[8]
    DIRECTION INPUT ;
    USE SIGNAL ;
    PORT
      LAYER M4 ;
        RECT  0 31.536 0.084 31.56 ;
    END
  END i[8]
  PIN i[90]
    DIRECTION INPUT ;
    USE SIGNAL ;
    PORT
      LAYER M4 ;
        RECT  0 24.048 0.084 24.072 ;
    END
  END i[90]
  PIN i[91]
    DIRECTION INPUT ;
    USE SIGNAL ;
    PORT
      LAYER M4 ;
        RECT  0 24.144 0.084 24.168 ;
    END
  END i[91]
  PIN i[92]
    DIRECTION INPUT ;
    USE SIGNAL ;
    PORT
      LAYER M4 ;
        RECT  0 24.24 0.084 24.264 ;
    END
  END i[92]
  PIN i[93]
    DIRECTION INPUT ;
    USE SIGNAL ;
    PORT
      LAYER M4 ;
        RECT  0 24.336 0.084 24.36 ;
    END
  END i[93]
  PIN i[94]
    DIRECTION INPUT ;
    USE SIGNAL ;
    PORT
      LAYER M4 ;
        RECT  0 24.432 0.084 24.456 ;
    END
  END i[94]
  PIN i[95]
    DIRECTION INPUT ;
    USE SIGNAL ;
    PORT
      LAYER M4 ;
        RECT  0 24.528 0.084 24.552 ;
    END
  END i[95]
  PIN i[96]
    DIRECTION INPUT ;
    USE SIGNAL ;
    PORT
      LAYER M4 ;
        RECT  0 18.48 0.084 18.504 ;
    END
  END i[96]
  PIN i[97]
    DIRECTION INPUT ;
    USE SIGNAL ;
    PORT
      LAYER M4 ;
        RECT  0 18.576 0.084 18.6 ;
    END
  END i[97]
  PIN i[98]
    DIRECTION INPUT ;
    USE SIGNAL ;
    PORT
      LAYER M4 ;
        RECT  0 18.672 0.084 18.696 ;
    END
  END i[98]
  PIN i[99]
    DIRECTION INPUT ;
    USE SIGNAL ;
    PORT
      LAYER M4 ;
        RECT  0 18.768 0.084 18.792 ;
    END
  END i[99]
  PIN i[9]
    DIRECTION INPUT ;
    USE SIGNAL ;
    PORT
      LAYER M4 ;
        RECT  0 31.632 0.084 31.656 ;
    END
  END i[9]
  PIN o[0]
    DIRECTION OUTPUT ;
    USE SIGNAL ;
    PORT
      LAYER M4 ;
        RECT  21.516 9.936 21.6 9.96 ;
    END
  END o[0]
  PIN o[100]
    DIRECTION OUTPUT ;
    USE SIGNAL ;
    PORT
      LAYER M4 ;
        RECT  21.516 13.392 21.6 13.416 ;
    END
  END o[100]
  PIN o[101]
    DIRECTION OUTPUT ;
    USE SIGNAL ;
    PORT
      LAYER M4 ;
        RECT  21.516 13.488 21.6 13.512 ;
    END
  END o[101]
  PIN o[102]
    DIRECTION OUTPUT ;
    USE SIGNAL ;
    PORT
      LAYER M4 ;
        RECT  21.516 13.584 21.6 13.608 ;
    END
  END o[102]
  PIN o[103]
    DIRECTION OUTPUT ;
    USE SIGNAL ;
    PORT
      LAYER M4 ;
        RECT  21.516 13.68 21.6 13.704 ;
    END
  END o[103]
  PIN o[104]
    DIRECTION OUTPUT ;
    USE SIGNAL ;
    PORT
      LAYER M4 ;
        RECT  21.516 13.776 21.6 13.8 ;
    END
  END o[104]
  PIN o[105]
    DIRECTION OUTPUT ;
    USE SIGNAL ;
    PORT
      LAYER M4 ;
        RECT  21.516 13.872 21.6 13.896 ;
    END
  END o[105]
  PIN o[106]
    DIRECTION OUTPUT ;
    USE SIGNAL ;
    PORT
      LAYER M4 ;
        RECT  21.516 13.968 21.6 13.992 ;
    END
  END o[106]
  PIN o[107]
    DIRECTION OUTPUT ;
    USE SIGNAL ;
    PORT
      LAYER M4 ;
        RECT  21.516 14.064 21.6 14.088 ;
    END
  END o[107]
  PIN o[108]
    DIRECTION OUTPUT ;
    USE SIGNAL ;
    PORT
      LAYER M4 ;
        RECT  21.516 14.16 21.6 14.184 ;
    END
  END o[108]
  PIN o[109]
    DIRECTION OUTPUT ;
    USE SIGNAL ;
    PORT
      LAYER M4 ;
        RECT  21.516 14.256 21.6 14.28 ;
    END
  END o[109]
  PIN o[10]
    DIRECTION OUTPUT ;
    USE SIGNAL ;
    PORT
      LAYER M4 ;
        RECT  21.516 10.896 21.6 10.92 ;
    END
  END o[10]
  PIN o[110]
    DIRECTION OUTPUT ;
    USE SIGNAL ;
    PORT
      LAYER M4 ;
        RECT  21.516 14.352 21.6 14.376 ;
    END
  END o[110]
  PIN o[111]
    DIRECTION OUTPUT ;
    USE SIGNAL ;
    PORT
      LAYER M4 ;
        RECT  21.516 14.448 21.6 14.472 ;
    END
  END o[111]
  PIN o[112]
    DIRECTION OUTPUT ;
    USE SIGNAL ;
    PORT
      LAYER M4 ;
        RECT  21.516 14.544 21.6 14.568 ;
    END
  END o[112]
  PIN o[113]
    DIRECTION OUTPUT ;
    USE SIGNAL ;
    PORT
      LAYER M4 ;
        RECT  21.516 14.64 21.6 14.664 ;
    END
  END o[113]
  PIN o[114]
    DIRECTION OUTPUT ;
    USE SIGNAL ;
    PORT
      LAYER M4 ;
        RECT  21.516 14.736 21.6 14.76 ;
    END
  END o[114]
  PIN o[115]
    DIRECTION OUTPUT ;
    USE SIGNAL ;
    PORT
      LAYER M4 ;
        RECT  21.516 14.832 21.6 14.856 ;
    END
  END o[115]
  PIN o[116]
    DIRECTION OUTPUT ;
    USE SIGNAL ;
    PORT
      LAYER M4 ;
        RECT  21.516 14.928 21.6 14.952 ;
    END
  END o[116]
  PIN o[117]
    DIRECTION OUTPUT ;
    USE SIGNAL ;
    PORT
      LAYER M4 ;
        RECT  21.516 15.024 21.6 15.048 ;
    END
  END o[117]
  PIN o[118]
    DIRECTION OUTPUT ;
    USE SIGNAL ;
    PORT
      LAYER M4 ;
        RECT  21.516 15.12 21.6 15.144 ;
    END
  END o[118]
  PIN o[119]
    DIRECTION OUTPUT ;
    USE SIGNAL ;
    PORT
      LAYER M4 ;
        RECT  21.516 15.216 21.6 15.24 ;
    END
  END o[119]
  PIN o[11]
    DIRECTION OUTPUT ;
    USE SIGNAL ;
    PORT
      LAYER M4 ;
        RECT  21.516 10.992 21.6 11.016 ;
    END
  END o[11]
  PIN o[120]
    DIRECTION OUTPUT ;
    USE SIGNAL ;
    PORT
      LAYER M4 ;
        RECT  21.516 15.312 21.6 15.336 ;
    END
  END o[120]
  PIN o[121]
    DIRECTION OUTPUT ;
    USE SIGNAL ;
    PORT
      LAYER M4 ;
        RECT  21.516 15.408 21.6 15.432 ;
    END
  END o[121]
  PIN o[122]
    DIRECTION OUTPUT ;
    USE SIGNAL ;
    PORT
      LAYER M4 ;
        RECT  21.516 15.504 21.6 15.528 ;
    END
  END o[122]
  PIN o[123]
    DIRECTION OUTPUT ;
    USE SIGNAL ;
    PORT
      LAYER M4 ;
        RECT  21.516 15.6 21.6 15.624 ;
    END
  END o[123]
  PIN o[124]
    DIRECTION OUTPUT ;
    USE SIGNAL ;
    PORT
      LAYER M4 ;
        RECT  21.516 15.696 21.6 15.72 ;
    END
  END o[124]
  PIN o[125]
    DIRECTION OUTPUT ;
    USE SIGNAL ;
    PORT
      LAYER M4 ;
        RECT  21.516 15.792 21.6 15.816 ;
    END
  END o[125]
  PIN o[126]
    DIRECTION OUTPUT ;
    USE SIGNAL ;
    PORT
      LAYER M4 ;
        RECT  21.516 15.888 21.6 15.912 ;
    END
  END o[126]
  PIN o[127]
    DIRECTION OUTPUT ;
    USE SIGNAL ;
    PORT
      LAYER M4 ;
        RECT  21.516 15.984 21.6 16.008 ;
    END
  END o[127]
  PIN o[128]
    DIRECTION OUTPUT ;
    USE SIGNAL ;
    PORT
      LAYER M4 ;
        RECT  21.516 16.08 21.6 16.104 ;
    END
  END o[128]
  PIN o[129]
    DIRECTION OUTPUT ;
    USE SIGNAL ;
    PORT
      LAYER M4 ;
        RECT  21.516 16.176 21.6 16.2 ;
    END
  END o[129]
  PIN o[12]
    DIRECTION OUTPUT ;
    USE SIGNAL ;
    PORT
      LAYER M4 ;
        RECT  21.516 11.088 21.6 11.112 ;
    END
  END o[12]
  PIN o[130]
    DIRECTION OUTPUT ;
    USE SIGNAL ;
    PORT
      LAYER M4 ;
        RECT  21.516 16.272 21.6 16.296 ;
    END
  END o[130]
  PIN o[131]
    DIRECTION OUTPUT ;
    USE SIGNAL ;
    PORT
      LAYER M4 ;
        RECT  21.516 16.368 21.6 16.392 ;
    END
  END o[131]
  PIN o[132]
    DIRECTION OUTPUT ;
    USE SIGNAL ;
    PORT
      LAYER M4 ;
        RECT  21.516 16.464 21.6 16.488 ;
    END
  END o[132]
  PIN o[133]
    DIRECTION OUTPUT ;
    USE SIGNAL ;
    PORT
      LAYER M4 ;
        RECT  21.516 16.56 21.6 16.584 ;
    END
  END o[133]
  PIN o[134]
    DIRECTION OUTPUT ;
    USE SIGNAL ;
    PORT
      LAYER M4 ;
        RECT  21.516 16.656 21.6 16.68 ;
    END
  END o[134]
  PIN o[135]
    DIRECTION OUTPUT ;
    USE SIGNAL ;
    PORT
      LAYER M4 ;
        RECT  21.516 16.752 21.6 16.776 ;
    END
  END o[135]
  PIN o[136]
    DIRECTION OUTPUT ;
    USE SIGNAL ;
    PORT
      LAYER M4 ;
        RECT  21.516 16.848 21.6 16.872 ;
    END
  END o[136]
  PIN o[137]
    DIRECTION OUTPUT ;
    USE SIGNAL ;
    PORT
      LAYER M4 ;
        RECT  21.516 16.944 21.6 16.968 ;
    END
  END o[137]
  PIN o[138]
    DIRECTION OUTPUT ;
    USE SIGNAL ;
    PORT
      LAYER M4 ;
        RECT  21.516 17.04 21.6 17.064 ;
    END
  END o[138]
  PIN o[139]
    DIRECTION OUTPUT ;
    USE SIGNAL ;
    PORT
      LAYER M4 ;
        RECT  21.516 17.136 21.6 17.16 ;
    END
  END o[139]
  PIN o[13]
    DIRECTION OUTPUT ;
    USE SIGNAL ;
    PORT
      LAYER M4 ;
        RECT  21.516 11.184 21.6 11.208 ;
    END
  END o[13]
  PIN o[140]
    DIRECTION OUTPUT ;
    USE SIGNAL ;
    PORT
      LAYER M4 ;
        RECT  21.516 17.232 21.6 17.256 ;
    END
  END o[140]
  PIN o[141]
    DIRECTION OUTPUT ;
    USE SIGNAL ;
    PORT
      LAYER M4 ;
        RECT  21.516 17.328 21.6 17.352 ;
    END
  END o[141]
  PIN o[142]
    DIRECTION OUTPUT ;
    USE SIGNAL ;
    PORT
      LAYER M4 ;
        RECT  21.516 17.424 21.6 17.448 ;
    END
  END o[142]
  PIN o[143]
    DIRECTION OUTPUT ;
    USE SIGNAL ;
    PORT
      LAYER M4 ;
        RECT  21.516 17.52 21.6 17.544 ;
    END
  END o[143]
  PIN o[144]
    DIRECTION OUTPUT ;
    USE SIGNAL ;
    PORT
      LAYER M4 ;
        RECT  21.516 17.616 21.6 17.64 ;
    END
  END o[144]
  PIN o[145]
    DIRECTION OUTPUT ;
    USE SIGNAL ;
    PORT
      LAYER M4 ;
        RECT  21.516 17.712 21.6 17.736 ;
    END
  END o[145]
  PIN o[146]
    DIRECTION OUTPUT ;
    USE SIGNAL ;
    PORT
      LAYER M4 ;
        RECT  21.516 17.808 21.6 17.832 ;
    END
  END o[146]
  PIN o[147]
    DIRECTION OUTPUT ;
    USE SIGNAL ;
    PORT
      LAYER M4 ;
        RECT  21.516 17.904 21.6 17.928 ;
    END
  END o[147]
  PIN o[148]
    DIRECTION OUTPUT ;
    USE SIGNAL ;
    PORT
      LAYER M4 ;
        RECT  21.516 18 21.6 18.024 ;
    END
  END o[148]
  PIN o[149]
    DIRECTION OUTPUT ;
    USE SIGNAL ;
    PORT
      LAYER M4 ;
        RECT  21.516 18.096 21.6 18.12 ;
    END
  END o[149]
  PIN o[14]
    DIRECTION OUTPUT ;
    USE SIGNAL ;
    PORT
      LAYER M4 ;
        RECT  21.516 11.28 21.6 11.304 ;
    END
  END o[14]
  PIN o[150]
    DIRECTION OUTPUT ;
    USE SIGNAL ;
    PORT
      LAYER M4 ;
        RECT  21.516 18.192 21.6 18.216 ;
    END
  END o[150]
  PIN o[151]
    DIRECTION OUTPUT ;
    USE SIGNAL ;
    PORT
      LAYER M4 ;
        RECT  21.516 18.288 21.6 18.312 ;
    END
  END o[151]
  PIN o[152]
    DIRECTION OUTPUT ;
    USE SIGNAL ;
    PORT
      LAYER M4 ;
        RECT  21.516 18.384 21.6 18.408 ;
    END
  END o[152]
  PIN o[153]
    DIRECTION OUTPUT ;
    USE SIGNAL ;
    PORT
      LAYER M4 ;
        RECT  21.516 18.48 21.6 18.504 ;
    END
  END o[153]
  PIN o[154]
    DIRECTION OUTPUT ;
    USE SIGNAL ;
    PORT
      LAYER M4 ;
        RECT  21.516 18.576 21.6 18.6 ;
    END
  END o[154]
  PIN o[155]
    DIRECTION OUTPUT ;
    USE SIGNAL ;
    PORT
      LAYER M4 ;
        RECT  21.516 18.672 21.6 18.696 ;
    END
  END o[155]
  PIN o[156]
    DIRECTION OUTPUT ;
    USE SIGNAL ;
    PORT
      LAYER M4 ;
        RECT  21.516 18.768 21.6 18.792 ;
    END
  END o[156]
  PIN o[157]
    DIRECTION OUTPUT ;
    USE SIGNAL ;
    PORT
      LAYER M4 ;
        RECT  21.516 18.864 21.6 18.888 ;
    END
  END o[157]
  PIN o[158]
    DIRECTION OUTPUT ;
    USE SIGNAL ;
    PORT
      LAYER M4 ;
        RECT  21.516 18.96 21.6 18.984 ;
    END
  END o[158]
  PIN o[159]
    DIRECTION OUTPUT ;
    USE SIGNAL ;
    PORT
      LAYER M4 ;
        RECT  21.516 19.056 21.6 19.08 ;
    END
  END o[159]
  PIN o[15]
    DIRECTION OUTPUT ;
    USE SIGNAL ;
    PORT
      LAYER M4 ;
        RECT  21.516 11.376 21.6 11.4 ;
    END
  END o[15]
  PIN o[160]
    DIRECTION OUTPUT ;
    USE SIGNAL ;
    PORT
      LAYER M4 ;
        RECT  21.516 0.72 21.6 0.744 ;
    END
  END o[160]
  PIN o[161]
    DIRECTION OUTPUT ;
    USE SIGNAL ;
    PORT
      LAYER M4 ;
        RECT  21.516 0.816 21.6 0.84 ;
    END
  END o[161]
  PIN o[162]
    DIRECTION OUTPUT ;
    USE SIGNAL ;
    PORT
      LAYER M4 ;
        RECT  21.516 0.912 21.6 0.936 ;
    END
  END o[162]
  PIN o[163]
    DIRECTION OUTPUT ;
    USE SIGNAL ;
    PORT
      LAYER M4 ;
        RECT  21.516 1.008 21.6 1.032 ;
    END
  END o[163]
  PIN o[164]
    DIRECTION OUTPUT ;
    USE SIGNAL ;
    PORT
      LAYER M4 ;
        RECT  21.516 1.104 21.6 1.128 ;
    END
  END o[164]
  PIN o[165]
    DIRECTION OUTPUT ;
    USE SIGNAL ;
    PORT
      LAYER M4 ;
        RECT  21.516 1.2 21.6 1.224 ;
    END
  END o[165]
  PIN o[166]
    DIRECTION OUTPUT ;
    USE SIGNAL ;
    PORT
      LAYER M4 ;
        RECT  21.516 1.296 21.6 1.32 ;
    END
  END o[166]
  PIN o[167]
    DIRECTION OUTPUT ;
    USE SIGNAL ;
    PORT
      LAYER M4 ;
        RECT  21.516 1.392 21.6 1.416 ;
    END
  END o[167]
  PIN o[168]
    DIRECTION OUTPUT ;
    USE SIGNAL ;
    PORT
      LAYER M4 ;
        RECT  21.516 1.488 21.6 1.512 ;
    END
  END o[168]
  PIN o[169]
    DIRECTION OUTPUT ;
    USE SIGNAL ;
    PORT
      LAYER M4 ;
        RECT  21.516 1.584 21.6 1.608 ;
    END
  END o[169]
  PIN o[16]
    DIRECTION OUTPUT ;
    USE SIGNAL ;
    PORT
      LAYER M4 ;
        RECT  21.516 11.472 21.6 11.496 ;
    END
  END o[16]
  PIN o[170]
    DIRECTION OUTPUT ;
    USE SIGNAL ;
    PORT
      LAYER M4 ;
        RECT  21.516 1.68 21.6 1.704 ;
    END
  END o[170]
  PIN o[171]
    DIRECTION OUTPUT ;
    USE SIGNAL ;
    PORT
      LAYER M4 ;
        RECT  21.516 1.776 21.6 1.8 ;
    END
  END o[171]
  PIN o[172]
    DIRECTION OUTPUT ;
    USE SIGNAL ;
    PORT
      LAYER M4 ;
        RECT  21.516 1.872 21.6 1.896 ;
    END
  END o[172]
  PIN o[173]
    DIRECTION OUTPUT ;
    USE SIGNAL ;
    PORT
      LAYER M4 ;
        RECT  21.516 1.968 21.6 1.992 ;
    END
  END o[173]
  PIN o[174]
    DIRECTION OUTPUT ;
    USE SIGNAL ;
    PORT
      LAYER M4 ;
        RECT  21.516 2.064 21.6 2.088 ;
    END
  END o[174]
  PIN o[175]
    DIRECTION OUTPUT ;
    USE SIGNAL ;
    PORT
      LAYER M4 ;
        RECT  21.516 2.16 21.6 2.184 ;
    END
  END o[175]
  PIN o[176]
    DIRECTION OUTPUT ;
    USE SIGNAL ;
    PORT
      LAYER M4 ;
        RECT  21.516 2.256 21.6 2.28 ;
    END
  END o[176]
  PIN o[177]
    DIRECTION OUTPUT ;
    USE SIGNAL ;
    PORT
      LAYER M4 ;
        RECT  21.516 2.352 21.6 2.376 ;
    END
  END o[177]
  PIN o[178]
    DIRECTION OUTPUT ;
    USE SIGNAL ;
    PORT
      LAYER M4 ;
        RECT  21.516 2.448 21.6 2.472 ;
    END
  END o[178]
  PIN o[179]
    DIRECTION OUTPUT ;
    USE SIGNAL ;
    PORT
      LAYER M4 ;
        RECT  21.516 2.544 21.6 2.568 ;
    END
  END o[179]
  PIN o[17]
    DIRECTION OUTPUT ;
    USE SIGNAL ;
    PORT
      LAYER M4 ;
        RECT  21.516 11.568 21.6 11.592 ;
    END
  END o[17]
  PIN o[180]
    DIRECTION OUTPUT ;
    USE SIGNAL ;
    PORT
      LAYER M4 ;
        RECT  21.516 2.64 21.6 2.664 ;
    END
  END o[180]
  PIN o[181]
    DIRECTION OUTPUT ;
    USE SIGNAL ;
    PORT
      LAYER M4 ;
        RECT  21.516 2.736 21.6 2.76 ;
    END
  END o[181]
  PIN o[182]
    DIRECTION OUTPUT ;
    USE SIGNAL ;
    PORT
      LAYER M4 ;
        RECT  21.516 2.832 21.6 2.856 ;
    END
  END o[182]
  PIN o[183]
    DIRECTION OUTPUT ;
    USE SIGNAL ;
    PORT
      LAYER M4 ;
        RECT  21.516 2.928 21.6 2.952 ;
    END
  END o[183]
  PIN o[184]
    DIRECTION OUTPUT ;
    USE SIGNAL ;
    PORT
      LAYER M4 ;
        RECT  21.516 3.024 21.6 3.048 ;
    END
  END o[184]
  PIN o[185]
    DIRECTION OUTPUT ;
    USE SIGNAL ;
    PORT
      LAYER M4 ;
        RECT  21.516 3.12 21.6 3.144 ;
    END
  END o[185]
  PIN o[186]
    DIRECTION OUTPUT ;
    USE SIGNAL ;
    PORT
      LAYER M4 ;
        RECT  21.516 3.216 21.6 3.24 ;
    END
  END o[186]
  PIN o[187]
    DIRECTION OUTPUT ;
    USE SIGNAL ;
    PORT
      LAYER M4 ;
        RECT  21.516 3.312 21.6 3.336 ;
    END
  END o[187]
  PIN o[188]
    DIRECTION OUTPUT ;
    USE SIGNAL ;
    PORT
      LAYER M4 ;
        RECT  21.516 3.408 21.6 3.432 ;
    END
  END o[188]
  PIN o[189]
    DIRECTION OUTPUT ;
    USE SIGNAL ;
    PORT
      LAYER M4 ;
        RECT  21.516 3.504 21.6 3.528 ;
    END
  END o[189]
  PIN o[18]
    DIRECTION OUTPUT ;
    USE SIGNAL ;
    PORT
      LAYER M4 ;
        RECT  21.516 11.664 21.6 11.688 ;
    END
  END o[18]
  PIN o[190]
    DIRECTION OUTPUT ;
    USE SIGNAL ;
    PORT
      LAYER M4 ;
        RECT  21.516 3.6 21.6 3.624 ;
    END
  END o[190]
  PIN o[191]
    DIRECTION OUTPUT ;
    USE SIGNAL ;
    PORT
      LAYER M4 ;
        RECT  21.516 3.696 21.6 3.72 ;
    END
  END o[191]
  PIN o[192]
    DIRECTION OUTPUT ;
    USE SIGNAL ;
    PORT
      LAYER M4 ;
        RECT  21.516 3.792 21.6 3.816 ;
    END
  END o[192]
  PIN o[193]
    DIRECTION OUTPUT ;
    USE SIGNAL ;
    PORT
      LAYER M4 ;
        RECT  21.516 3.888 21.6 3.912 ;
    END
  END o[193]
  PIN o[194]
    DIRECTION OUTPUT ;
    USE SIGNAL ;
    PORT
      LAYER M4 ;
        RECT  21.516 3.984 21.6 4.008 ;
    END
  END o[194]
  PIN o[195]
    DIRECTION OUTPUT ;
    USE SIGNAL ;
    PORT
      LAYER M4 ;
        RECT  21.516 4.08 21.6 4.104 ;
    END
  END o[195]
  PIN o[196]
    DIRECTION OUTPUT ;
    USE SIGNAL ;
    PORT
      LAYER M4 ;
        RECT  21.516 4.176 21.6 4.2 ;
    END
  END o[196]
  PIN o[197]
    DIRECTION OUTPUT ;
    USE SIGNAL ;
    PORT
      LAYER M4 ;
        RECT  21.516 4.272 21.6 4.296 ;
    END
  END o[197]
  PIN o[198]
    DIRECTION OUTPUT ;
    USE SIGNAL ;
    PORT
      LAYER M4 ;
        RECT  21.516 4.368 21.6 4.392 ;
    END
  END o[198]
  PIN o[199]
    DIRECTION OUTPUT ;
    USE SIGNAL ;
    PORT
      LAYER M4 ;
        RECT  21.516 4.464 21.6 4.488 ;
    END
  END o[199]
  PIN o[19]
    DIRECTION OUTPUT ;
    USE SIGNAL ;
    PORT
      LAYER M4 ;
        RECT  21.516 11.76 21.6 11.784 ;
    END
  END o[19]
  PIN o[1]
    DIRECTION OUTPUT ;
    USE SIGNAL ;
    PORT
      LAYER M4 ;
        RECT  21.516 10.032 21.6 10.056 ;
    END
  END o[1]
  PIN o[200]
    DIRECTION OUTPUT ;
    USE SIGNAL ;
    PORT
      LAYER M4 ;
        RECT  21.516 4.56 21.6 4.584 ;
    END
  END o[200]
  PIN o[201]
    DIRECTION OUTPUT ;
    USE SIGNAL ;
    PORT
      LAYER M4 ;
        RECT  21.516 4.656 21.6 4.68 ;
    END
  END o[201]
  PIN o[202]
    DIRECTION OUTPUT ;
    USE SIGNAL ;
    PORT
      LAYER M4 ;
        RECT  21.516 4.752 21.6 4.776 ;
    END
  END o[202]
  PIN o[203]
    DIRECTION OUTPUT ;
    USE SIGNAL ;
    PORT
      LAYER M4 ;
        RECT  21.516 4.848 21.6 4.872 ;
    END
  END o[203]
  PIN o[204]
    DIRECTION OUTPUT ;
    USE SIGNAL ;
    PORT
      LAYER M4 ;
        RECT  21.516 4.944 21.6 4.968 ;
    END
  END o[204]
  PIN o[205]
    DIRECTION OUTPUT ;
    USE SIGNAL ;
    PORT
      LAYER M4 ;
        RECT  21.516 5.04 21.6 5.064 ;
    END
  END o[205]
  PIN o[206]
    DIRECTION OUTPUT ;
    USE SIGNAL ;
    PORT
      LAYER M4 ;
        RECT  21.516 5.136 21.6 5.16 ;
    END
  END o[206]
  PIN o[207]
    DIRECTION OUTPUT ;
    USE SIGNAL ;
    PORT
      LAYER M4 ;
        RECT  21.516 5.232 21.6 5.256 ;
    END
  END o[207]
  PIN o[208]
    DIRECTION OUTPUT ;
    USE SIGNAL ;
    PORT
      LAYER M4 ;
        RECT  21.516 5.328 21.6 5.352 ;
    END
  END o[208]
  PIN o[209]
    DIRECTION OUTPUT ;
    USE SIGNAL ;
    PORT
      LAYER M4 ;
        RECT  21.516 5.424 21.6 5.448 ;
    END
  END o[209]
  PIN o[20]
    DIRECTION OUTPUT ;
    USE SIGNAL ;
    PORT
      LAYER M4 ;
        RECT  21.516 11.856 21.6 11.88 ;
    END
  END o[20]
  PIN o[210]
    DIRECTION OUTPUT ;
    USE SIGNAL ;
    PORT
      LAYER M4 ;
        RECT  21.516 5.52 21.6 5.544 ;
    END
  END o[210]
  PIN o[211]
    DIRECTION OUTPUT ;
    USE SIGNAL ;
    PORT
      LAYER M4 ;
        RECT  21.516 5.616 21.6 5.64 ;
    END
  END o[211]
  PIN o[212]
    DIRECTION OUTPUT ;
    USE SIGNAL ;
    PORT
      LAYER M4 ;
        RECT  21.516 5.712 21.6 5.736 ;
    END
  END o[212]
  PIN o[213]
    DIRECTION OUTPUT ;
    USE SIGNAL ;
    PORT
      LAYER M4 ;
        RECT  21.516 5.808 21.6 5.832 ;
    END
  END o[213]
  PIN o[214]
    DIRECTION OUTPUT ;
    USE SIGNAL ;
    PORT
      LAYER M4 ;
        RECT  21.516 5.904 21.6 5.928 ;
    END
  END o[214]
  PIN o[215]
    DIRECTION OUTPUT ;
    USE SIGNAL ;
    PORT
      LAYER M4 ;
        RECT  21.516 6 21.6 6.024 ;
    END
  END o[215]
  PIN o[216]
    DIRECTION OUTPUT ;
    USE SIGNAL ;
    PORT
      LAYER M4 ;
        RECT  21.516 6.096 21.6 6.12 ;
    END
  END o[216]
  PIN o[217]
    DIRECTION OUTPUT ;
    USE SIGNAL ;
    PORT
      LAYER M4 ;
        RECT  21.516 6.192 21.6 6.216 ;
    END
  END o[217]
  PIN o[218]
    DIRECTION OUTPUT ;
    USE SIGNAL ;
    PORT
      LAYER M4 ;
        RECT  21.516 6.288 21.6 6.312 ;
    END
  END o[218]
  PIN o[219]
    DIRECTION OUTPUT ;
    USE SIGNAL ;
    PORT
      LAYER M4 ;
        RECT  21.516 6.384 21.6 6.408 ;
    END
  END o[219]
  PIN o[21]
    DIRECTION OUTPUT ;
    USE SIGNAL ;
    PORT
      LAYER M4 ;
        RECT  21.516 11.952 21.6 11.976 ;
    END
  END o[21]
  PIN o[220]
    DIRECTION OUTPUT ;
    USE SIGNAL ;
    PORT
      LAYER M4 ;
        RECT  21.516 6.48 21.6 6.504 ;
    END
  END o[220]
  PIN o[221]
    DIRECTION OUTPUT ;
    USE SIGNAL ;
    PORT
      LAYER M4 ;
        RECT  21.516 6.576 21.6 6.6 ;
    END
  END o[221]
  PIN o[222]
    DIRECTION OUTPUT ;
    USE SIGNAL ;
    PORT
      LAYER M4 ;
        RECT  21.516 6.672 21.6 6.696 ;
    END
  END o[222]
  PIN o[223]
    DIRECTION OUTPUT ;
    USE SIGNAL ;
    PORT
      LAYER M4 ;
        RECT  21.516 6.768 21.6 6.792 ;
    END
  END o[223]
  PIN o[224]
    DIRECTION OUTPUT ;
    USE SIGNAL ;
    PORT
      LAYER M4 ;
        RECT  21.516 29.136 21.6 29.16 ;
    END
  END o[224]
  PIN o[225]
    DIRECTION OUTPUT ;
    USE SIGNAL ;
    PORT
      LAYER M4 ;
        RECT  21.516 29.232 21.6 29.256 ;
    END
  END o[225]
  PIN o[226]
    DIRECTION OUTPUT ;
    USE SIGNAL ;
    PORT
      LAYER M4 ;
        RECT  21.516 29.328 21.6 29.352 ;
    END
  END o[226]
  PIN o[227]
    DIRECTION OUTPUT ;
    USE SIGNAL ;
    PORT
      LAYER M4 ;
        RECT  21.516 29.424 21.6 29.448 ;
    END
  END o[227]
  PIN o[228]
    DIRECTION OUTPUT ;
    USE SIGNAL ;
    PORT
      LAYER M4 ;
        RECT  21.516 29.52 21.6 29.544 ;
    END
  END o[228]
  PIN o[229]
    DIRECTION OUTPUT ;
    USE SIGNAL ;
    PORT
      LAYER M4 ;
        RECT  21.516 29.616 21.6 29.64 ;
    END
  END o[229]
  PIN o[22]
    DIRECTION OUTPUT ;
    USE SIGNAL ;
    PORT
      LAYER M4 ;
        RECT  21.516 12.048 21.6 12.072 ;
    END
  END o[22]
  PIN o[230]
    DIRECTION OUTPUT ;
    USE SIGNAL ;
    PORT
      LAYER M4 ;
        RECT  21.516 29.712 21.6 29.736 ;
    END
  END o[230]
  PIN o[231]
    DIRECTION OUTPUT ;
    USE SIGNAL ;
    PORT
      LAYER M4 ;
        RECT  21.516 29.808 21.6 29.832 ;
    END
  END o[231]
  PIN o[232]
    DIRECTION OUTPUT ;
    USE SIGNAL ;
    PORT
      LAYER M4 ;
        RECT  21.516 29.904 21.6 29.928 ;
    END
  END o[232]
  PIN o[233]
    DIRECTION OUTPUT ;
    USE SIGNAL ;
    PORT
      LAYER M4 ;
        RECT  21.516 30 21.6 30.024 ;
    END
  END o[233]
  PIN o[234]
    DIRECTION OUTPUT ;
    USE SIGNAL ;
    PORT
      LAYER M4 ;
        RECT  21.516 30.096 21.6 30.12 ;
    END
  END o[234]
  PIN o[235]
    DIRECTION OUTPUT ;
    USE SIGNAL ;
    PORT
      LAYER M4 ;
        RECT  21.516 30.192 21.6 30.216 ;
    END
  END o[235]
  PIN o[236]
    DIRECTION OUTPUT ;
    USE SIGNAL ;
    PORT
      LAYER M4 ;
        RECT  21.516 30.288 21.6 30.312 ;
    END
  END o[236]
  PIN o[237]
    DIRECTION OUTPUT ;
    USE SIGNAL ;
    PORT
      LAYER M4 ;
        RECT  21.516 30.384 21.6 30.408 ;
    END
  END o[237]
  PIN o[238]
    DIRECTION OUTPUT ;
    USE SIGNAL ;
    PORT
      LAYER M4 ;
        RECT  21.516 30.48 21.6 30.504 ;
    END
  END o[238]
  PIN o[239]
    DIRECTION OUTPUT ;
    USE SIGNAL ;
    PORT
      LAYER M4 ;
        RECT  21.516 30.576 21.6 30.6 ;
    END
  END o[239]
  PIN o[23]
    DIRECTION OUTPUT ;
    USE SIGNAL ;
    PORT
      LAYER M4 ;
        RECT  21.516 12.144 21.6 12.168 ;
    END
  END o[23]
  PIN o[240]
    DIRECTION OUTPUT ;
    USE SIGNAL ;
    PORT
      LAYER M4 ;
        RECT  21.516 30.672 21.6 30.696 ;
    END
  END o[240]
  PIN o[241]
    DIRECTION OUTPUT ;
    USE SIGNAL ;
    PORT
      LAYER M4 ;
        RECT  21.516 30.768 21.6 30.792 ;
    END
  END o[241]
  PIN o[242]
    DIRECTION OUTPUT ;
    USE SIGNAL ;
    PORT
      LAYER M4 ;
        RECT  21.516 30.864 21.6 30.888 ;
    END
  END o[242]
  PIN o[243]
    DIRECTION OUTPUT ;
    USE SIGNAL ;
    PORT
      LAYER M4 ;
        RECT  21.516 30.96 21.6 30.984 ;
    END
  END o[243]
  PIN o[244]
    DIRECTION OUTPUT ;
    USE SIGNAL ;
    PORT
      LAYER M4 ;
        RECT  21.516 31.056 21.6 31.08 ;
    END
  END o[244]
  PIN o[245]
    DIRECTION OUTPUT ;
    USE SIGNAL ;
    PORT
      LAYER M4 ;
        RECT  21.516 31.152 21.6 31.176 ;
    END
  END o[245]
  PIN o[246]
    DIRECTION OUTPUT ;
    USE SIGNAL ;
    PORT
      LAYER M4 ;
        RECT  21.516 31.248 21.6 31.272 ;
    END
  END o[246]
  PIN o[247]
    DIRECTION OUTPUT ;
    USE SIGNAL ;
    PORT
      LAYER M4 ;
        RECT  21.516 31.344 21.6 31.368 ;
    END
  END o[247]
  PIN o[248]
    DIRECTION OUTPUT ;
    USE SIGNAL ;
    PORT
      LAYER M4 ;
        RECT  21.516 31.44 21.6 31.464 ;
    END
  END o[248]
  PIN o[249]
    DIRECTION OUTPUT ;
    USE SIGNAL ;
    PORT
      LAYER M4 ;
        RECT  21.516 31.536 21.6 31.56 ;
    END
  END o[249]
  PIN o[24]
    DIRECTION OUTPUT ;
    USE SIGNAL ;
    PORT
      LAYER M4 ;
        RECT  21.516 12.24 21.6 12.264 ;
    END
  END o[24]
  PIN o[250]
    DIRECTION OUTPUT ;
    USE SIGNAL ;
    PORT
      LAYER M4 ;
        RECT  21.516 31.632 21.6 31.656 ;
    END
  END o[250]
  PIN o[251]
    DIRECTION OUTPUT ;
    USE SIGNAL ;
    PORT
      LAYER M4 ;
        RECT  21.516 31.728 21.6 31.752 ;
    END
  END o[251]
  PIN o[252]
    DIRECTION OUTPUT ;
    USE SIGNAL ;
    PORT
      LAYER M4 ;
        RECT  21.516 31.824 21.6 31.848 ;
    END
  END o[252]
  PIN o[253]
    DIRECTION OUTPUT ;
    USE SIGNAL ;
    PORT
      LAYER M4 ;
        RECT  21.516 31.92 21.6 31.944 ;
    END
  END o[253]
  PIN o[254]
    DIRECTION OUTPUT ;
    USE SIGNAL ;
    PORT
      LAYER M4 ;
        RECT  21.516 32.016 21.6 32.04 ;
    END
  END o[254]
  PIN o[255]
    DIRECTION OUTPUT ;
    USE SIGNAL ;
    PORT
      LAYER M4 ;
        RECT  21.516 32.112 21.6 32.136 ;
    END
  END o[255]
  PIN o[256]
    DIRECTION OUTPUT ;
    USE SIGNAL ;
    PORT
      LAYER M4 ;
        RECT  21.516 19.92 21.6 19.944 ;
    END
  END o[256]
  PIN o[257]
    DIRECTION OUTPUT ;
    USE SIGNAL ;
    PORT
      LAYER M4 ;
        RECT  21.516 20.016 21.6 20.04 ;
    END
  END o[257]
  PIN o[258]
    DIRECTION OUTPUT ;
    USE SIGNAL ;
    PORT
      LAYER M4 ;
        RECT  21.516 20.112 21.6 20.136 ;
    END
  END o[258]
  PIN o[259]
    DIRECTION OUTPUT ;
    USE SIGNAL ;
    PORT
      LAYER M4 ;
        RECT  21.516 20.208 21.6 20.232 ;
    END
  END o[259]
  PIN o[25]
    DIRECTION OUTPUT ;
    USE SIGNAL ;
    PORT
      LAYER M4 ;
        RECT  21.516 12.336 21.6 12.36 ;
    END
  END o[25]
  PIN o[260]
    DIRECTION OUTPUT ;
    USE SIGNAL ;
    PORT
      LAYER M4 ;
        RECT  21.516 20.304 21.6 20.328 ;
    END
  END o[260]
  PIN o[261]
    DIRECTION OUTPUT ;
    USE SIGNAL ;
    PORT
      LAYER M4 ;
        RECT  21.516 20.4 21.6 20.424 ;
    END
  END o[261]
  PIN o[262]
    DIRECTION OUTPUT ;
    USE SIGNAL ;
    PORT
      LAYER M4 ;
        RECT  21.516 20.496 21.6 20.52 ;
    END
  END o[262]
  PIN o[263]
    DIRECTION OUTPUT ;
    USE SIGNAL ;
    PORT
      LAYER M4 ;
        RECT  21.516 20.592 21.6 20.616 ;
    END
  END o[263]
  PIN o[264]
    DIRECTION OUTPUT ;
    USE SIGNAL ;
    PORT
      LAYER M4 ;
        RECT  21.516 20.688 21.6 20.712 ;
    END
  END o[264]
  PIN o[265]
    DIRECTION OUTPUT ;
    USE SIGNAL ;
    PORT
      LAYER M4 ;
        RECT  21.516 20.784 21.6 20.808 ;
    END
  END o[265]
  PIN o[266]
    DIRECTION OUTPUT ;
    USE SIGNAL ;
    PORT
      LAYER M4 ;
        RECT  21.516 20.88 21.6 20.904 ;
    END
  END o[266]
  PIN o[267]
    DIRECTION OUTPUT ;
    USE SIGNAL ;
    PORT
      LAYER M4 ;
        RECT  21.516 20.976 21.6 21 ;
    END
  END o[267]
  PIN o[268]
    DIRECTION OUTPUT ;
    USE SIGNAL ;
    PORT
      LAYER M4 ;
        RECT  21.516 21.072 21.6 21.096 ;
    END
  END o[268]
  PIN o[269]
    DIRECTION OUTPUT ;
    USE SIGNAL ;
    PORT
      LAYER M4 ;
        RECT  21.516 21.168 21.6 21.192 ;
    END
  END o[269]
  PIN o[26]
    DIRECTION OUTPUT ;
    USE SIGNAL ;
    PORT
      LAYER M4 ;
        RECT  21.516 12.432 21.6 12.456 ;
    END
  END o[26]
  PIN o[270]
    DIRECTION OUTPUT ;
    USE SIGNAL ;
    PORT
      LAYER M4 ;
        RECT  21.516 21.264 21.6 21.288 ;
    END
  END o[270]
  PIN o[271]
    DIRECTION OUTPUT ;
    USE SIGNAL ;
    PORT
      LAYER M4 ;
        RECT  21.516 21.36 21.6 21.384 ;
    END
  END o[271]
  PIN o[272]
    DIRECTION OUTPUT ;
    USE SIGNAL ;
    PORT
      LAYER M4 ;
        RECT  21.516 21.456 21.6 21.48 ;
    END
  END o[272]
  PIN o[273]
    DIRECTION OUTPUT ;
    USE SIGNAL ;
    PORT
      LAYER M4 ;
        RECT  21.516 21.552 21.6 21.576 ;
    END
  END o[273]
  PIN o[274]
    DIRECTION OUTPUT ;
    USE SIGNAL ;
    PORT
      LAYER M4 ;
        RECT  21.516 21.648 21.6 21.672 ;
    END
  END o[274]
  PIN o[275]
    DIRECTION OUTPUT ;
    USE SIGNAL ;
    PORT
      LAYER M4 ;
        RECT  21.516 21.744 21.6 21.768 ;
    END
  END o[275]
  PIN o[276]
    DIRECTION OUTPUT ;
    USE SIGNAL ;
    PORT
      LAYER M4 ;
        RECT  21.516 21.84 21.6 21.864 ;
    END
  END o[276]
  PIN o[277]
    DIRECTION OUTPUT ;
    USE SIGNAL ;
    PORT
      LAYER M4 ;
        RECT  21.516 21.936 21.6 21.96 ;
    END
  END o[277]
  PIN o[278]
    DIRECTION OUTPUT ;
    USE SIGNAL ;
    PORT
      LAYER M4 ;
        RECT  21.516 22.032 21.6 22.056 ;
    END
  END o[278]
  PIN o[279]
    DIRECTION OUTPUT ;
    USE SIGNAL ;
    PORT
      LAYER M4 ;
        RECT  21.516 22.128 21.6 22.152 ;
    END
  END o[279]
  PIN o[27]
    DIRECTION OUTPUT ;
    USE SIGNAL ;
    PORT
      LAYER M4 ;
        RECT  21.516 12.528 21.6 12.552 ;
    END
  END o[27]
  PIN o[280]
    DIRECTION OUTPUT ;
    USE SIGNAL ;
    PORT
      LAYER M4 ;
        RECT  21.516 22.224 21.6 22.248 ;
    END
  END o[280]
  PIN o[281]
    DIRECTION OUTPUT ;
    USE SIGNAL ;
    PORT
      LAYER M4 ;
        RECT  21.516 22.32 21.6 22.344 ;
    END
  END o[281]
  PIN o[282]
    DIRECTION OUTPUT ;
    USE SIGNAL ;
    PORT
      LAYER M4 ;
        RECT  21.516 22.416 21.6 22.44 ;
    END
  END o[282]
  PIN o[283]
    DIRECTION OUTPUT ;
    USE SIGNAL ;
    PORT
      LAYER M4 ;
        RECT  21.516 22.512 21.6 22.536 ;
    END
  END o[283]
  PIN o[284]
    DIRECTION OUTPUT ;
    USE SIGNAL ;
    PORT
      LAYER M4 ;
        RECT  21.516 22.608 21.6 22.632 ;
    END
  END o[284]
  PIN o[285]
    DIRECTION OUTPUT ;
    USE SIGNAL ;
    PORT
      LAYER M4 ;
        RECT  21.516 22.704 21.6 22.728 ;
    END
  END o[285]
  PIN o[286]
    DIRECTION OUTPUT ;
    USE SIGNAL ;
    PORT
      LAYER M4 ;
        RECT  21.516 22.8 21.6 22.824 ;
    END
  END o[286]
  PIN o[287]
    DIRECTION OUTPUT ;
    USE SIGNAL ;
    PORT
      LAYER M4 ;
        RECT  21.516 22.896 21.6 22.92 ;
    END
  END o[287]
  PIN o[288]
    DIRECTION OUTPUT ;
    USE SIGNAL ;
    PORT
      LAYER M4 ;
        RECT  21.516 22.992 21.6 23.016 ;
    END
  END o[288]
  PIN o[289]
    DIRECTION OUTPUT ;
    USE SIGNAL ;
    PORT
      LAYER M4 ;
        RECT  21.516 23.088 21.6 23.112 ;
    END
  END o[289]
  PIN o[28]
    DIRECTION OUTPUT ;
    USE SIGNAL ;
    PORT
      LAYER M4 ;
        RECT  21.516 12.624 21.6 12.648 ;
    END
  END o[28]
  PIN o[290]
    DIRECTION OUTPUT ;
    USE SIGNAL ;
    PORT
      LAYER M4 ;
        RECT  21.516 23.184 21.6 23.208 ;
    END
  END o[290]
  PIN o[291]
    DIRECTION OUTPUT ;
    USE SIGNAL ;
    PORT
      LAYER M4 ;
        RECT  21.516 23.28 21.6 23.304 ;
    END
  END o[291]
  PIN o[292]
    DIRECTION OUTPUT ;
    USE SIGNAL ;
    PORT
      LAYER M4 ;
        RECT  21.516 23.376 21.6 23.4 ;
    END
  END o[292]
  PIN o[293]
    DIRECTION OUTPUT ;
    USE SIGNAL ;
    PORT
      LAYER M4 ;
        RECT  21.516 23.472 21.6 23.496 ;
    END
  END o[293]
  PIN o[294]
    DIRECTION OUTPUT ;
    USE SIGNAL ;
    PORT
      LAYER M4 ;
        RECT  21.516 23.568 21.6 23.592 ;
    END
  END o[294]
  PIN o[295]
    DIRECTION OUTPUT ;
    USE SIGNAL ;
    PORT
      LAYER M4 ;
        RECT  21.516 23.664 21.6 23.688 ;
    END
  END o[295]
  PIN o[296]
    DIRECTION OUTPUT ;
    USE SIGNAL ;
    PORT
      LAYER M4 ;
        RECT  21.516 23.76 21.6 23.784 ;
    END
  END o[296]
  PIN o[297]
    DIRECTION OUTPUT ;
    USE SIGNAL ;
    PORT
      LAYER M4 ;
        RECT  21.516 23.856 21.6 23.88 ;
    END
  END o[297]
  PIN o[298]
    DIRECTION OUTPUT ;
    USE SIGNAL ;
    PORT
      LAYER M4 ;
        RECT  21.516 23.952 21.6 23.976 ;
    END
  END o[298]
  PIN o[299]
    DIRECTION OUTPUT ;
    USE SIGNAL ;
    PORT
      LAYER M4 ;
        RECT  21.516 24.048 21.6 24.072 ;
    END
  END o[299]
  PIN o[29]
    DIRECTION OUTPUT ;
    USE SIGNAL ;
    PORT
      LAYER M4 ;
        RECT  21.516 12.72 21.6 12.744 ;
    END
  END o[29]
  PIN o[2]
    DIRECTION OUTPUT ;
    USE SIGNAL ;
    PORT
      LAYER M4 ;
        RECT  21.516 10.128 21.6 10.152 ;
    END
  END o[2]
  PIN o[300]
    DIRECTION OUTPUT ;
    USE SIGNAL ;
    PORT
      LAYER M4 ;
        RECT  21.516 24.144 21.6 24.168 ;
    END
  END o[300]
  PIN o[301]
    DIRECTION OUTPUT ;
    USE SIGNAL ;
    PORT
      LAYER M4 ;
        RECT  21.516 24.24 21.6 24.264 ;
    END
  END o[301]
  PIN o[302]
    DIRECTION OUTPUT ;
    USE SIGNAL ;
    PORT
      LAYER M4 ;
        RECT  21.516 24.336 21.6 24.36 ;
    END
  END o[302]
  PIN o[303]
    DIRECTION OUTPUT ;
    USE SIGNAL ;
    PORT
      LAYER M4 ;
        RECT  21.516 24.432 21.6 24.456 ;
    END
  END o[303]
  PIN o[30]
    DIRECTION OUTPUT ;
    USE SIGNAL ;
    PORT
      LAYER M4 ;
        RECT  21.516 12.816 21.6 12.84 ;
    END
  END o[30]
  PIN o[31]
    DIRECTION OUTPUT ;
    USE SIGNAL ;
    PORT
      LAYER M4 ;
        RECT  21.516 12.912 21.6 12.936 ;
    END
  END o[31]
  PIN o[32]
    DIRECTION OUTPUT ;
    USE SIGNAL ;
    PORT
      LAYER M4 ;
        RECT  21.516 26.064 21.6 26.088 ;
    END
  END o[32]
  PIN o[33]
    DIRECTION OUTPUT ;
    USE SIGNAL ;
    PORT
      LAYER M4 ;
        RECT  21.516 26.16 21.6 26.184 ;
    END
  END o[33]
  PIN o[34]
    DIRECTION OUTPUT ;
    USE SIGNAL ;
    PORT
      LAYER M4 ;
        RECT  21.516 26.256 21.6 26.28 ;
    END
  END o[34]
  PIN o[35]
    DIRECTION OUTPUT ;
    USE SIGNAL ;
    PORT
      LAYER M4 ;
        RECT  21.516 26.352 21.6 26.376 ;
    END
  END o[35]
  PIN o[36]
    DIRECTION OUTPUT ;
    USE SIGNAL ;
    PORT
      LAYER M4 ;
        RECT  21.516 26.448 21.6 26.472 ;
    END
  END o[36]
  PIN o[37]
    DIRECTION OUTPUT ;
    USE SIGNAL ;
    PORT
      LAYER M4 ;
        RECT  21.516 26.544 21.6 26.568 ;
    END
  END o[37]
  PIN o[38]
    DIRECTION OUTPUT ;
    USE SIGNAL ;
    PORT
      LAYER M4 ;
        RECT  21.516 26.64 21.6 26.664 ;
    END
  END o[38]
  PIN o[39]
    DIRECTION OUTPUT ;
    USE SIGNAL ;
    PORT
      LAYER M4 ;
        RECT  21.516 26.736 21.6 26.76 ;
    END
  END o[39]
  PIN o[3]
    DIRECTION OUTPUT ;
    USE SIGNAL ;
    PORT
      LAYER M4 ;
        RECT  21.516 10.224 21.6 10.248 ;
    END
  END o[3]
  PIN o[40]
    DIRECTION OUTPUT ;
    USE SIGNAL ;
    PORT
      LAYER M4 ;
        RECT  21.516 26.832 21.6 26.856 ;
    END
  END o[40]
  PIN o[41]
    DIRECTION OUTPUT ;
    USE SIGNAL ;
    PORT
      LAYER M4 ;
        RECT  21.516 26.928 21.6 26.952 ;
    END
  END o[41]
  PIN o[42]
    DIRECTION OUTPUT ;
    USE SIGNAL ;
    PORT
      LAYER M4 ;
        RECT  21.516 27.024 21.6 27.048 ;
    END
  END o[42]
  PIN o[43]
    DIRECTION OUTPUT ;
    USE SIGNAL ;
    PORT
      LAYER M4 ;
        RECT  21.516 27.12 21.6 27.144 ;
    END
  END o[43]
  PIN o[44]
    DIRECTION OUTPUT ;
    USE SIGNAL ;
    PORT
      LAYER M4 ;
        RECT  21.516 27.216 21.6 27.24 ;
    END
  END o[44]
  PIN o[45]
    DIRECTION OUTPUT ;
    USE SIGNAL ;
    PORT
      LAYER M4 ;
        RECT  21.516 27.312 21.6 27.336 ;
    END
  END o[45]
  PIN o[46]
    DIRECTION OUTPUT ;
    USE SIGNAL ;
    PORT
      LAYER M4 ;
        RECT  21.516 27.408 21.6 27.432 ;
    END
  END o[46]
  PIN o[47]
    DIRECTION OUTPUT ;
    USE SIGNAL ;
    PORT
      LAYER M4 ;
        RECT  21.516 27.504 21.6 27.528 ;
    END
  END o[47]
  PIN o[48]
    DIRECTION OUTPUT ;
    USE SIGNAL ;
    PORT
      LAYER M4 ;
        RECT  21.516 27.6 21.6 27.624 ;
    END
  END o[48]
  PIN o[49]
    DIRECTION OUTPUT ;
    USE SIGNAL ;
    PORT
      LAYER M4 ;
        RECT  21.516 27.696 21.6 27.72 ;
    END
  END o[49]
  PIN o[4]
    DIRECTION OUTPUT ;
    USE SIGNAL ;
    PORT
      LAYER M4 ;
        RECT  21.516 10.32 21.6 10.344 ;
    END
  END o[4]
  PIN o[50]
    DIRECTION OUTPUT ;
    USE SIGNAL ;
    PORT
      LAYER M4 ;
        RECT  21.516 27.792 21.6 27.816 ;
    END
  END o[50]
  PIN o[51]
    DIRECTION OUTPUT ;
    USE SIGNAL ;
    PORT
      LAYER M4 ;
        RECT  21.516 27.888 21.6 27.912 ;
    END
  END o[51]
  PIN o[52]
    DIRECTION OUTPUT ;
    USE SIGNAL ;
    PORT
      LAYER M4 ;
        RECT  21.516 27.984 21.6 28.008 ;
    END
  END o[52]
  PIN o[53]
    DIRECTION OUTPUT ;
    USE SIGNAL ;
    PORT
      LAYER M4 ;
        RECT  21.516 28.08 21.6 28.104 ;
    END
  END o[53]
  PIN o[54]
    DIRECTION OUTPUT ;
    USE SIGNAL ;
    PORT
      LAYER M4 ;
        RECT  21.516 28.176 21.6 28.2 ;
    END
  END o[54]
  PIN o[55]
    DIRECTION OUTPUT ;
    USE SIGNAL ;
    PORT
      LAYER M4 ;
        RECT  21.516 28.272 21.6 28.296 ;
    END
  END o[55]
  PIN o[56]
    DIRECTION OUTPUT ;
    USE SIGNAL ;
    PORT
      LAYER M4 ;
        RECT  21.516 28.368 21.6 28.392 ;
    END
  END o[56]
  PIN o[57]
    DIRECTION OUTPUT ;
    USE SIGNAL ;
    PORT
      LAYER M4 ;
        RECT  21.516 28.464 21.6 28.488 ;
    END
  END o[57]
  PIN o[58]
    DIRECTION OUTPUT ;
    USE SIGNAL ;
    PORT
      LAYER M4 ;
        RECT  21.516 28.56 21.6 28.584 ;
    END
  END o[58]
  PIN o[59]
    DIRECTION OUTPUT ;
    USE SIGNAL ;
    PORT
      LAYER M4 ;
        RECT  21.516 28.656 21.6 28.68 ;
    END
  END o[59]
  PIN o[5]
    DIRECTION OUTPUT ;
    USE SIGNAL ;
    PORT
      LAYER M4 ;
        RECT  21.516 10.416 21.6 10.44 ;
    END
  END o[5]
  PIN o[60]
    DIRECTION OUTPUT ;
    USE SIGNAL ;
    PORT
      LAYER M4 ;
        RECT  21.516 28.752 21.6 28.776 ;
    END
  END o[60]
  PIN o[61]
    DIRECTION OUTPUT ;
    USE SIGNAL ;
    PORT
      LAYER M4 ;
        RECT  21.516 28.848 21.6 28.872 ;
    END
  END o[61]
  PIN o[62]
    DIRECTION OUTPUT ;
    USE SIGNAL ;
    PORT
      LAYER M4 ;
        RECT  21.516 28.944 21.6 28.968 ;
    END
  END o[62]
  PIN o[63]
    DIRECTION OUTPUT ;
    USE SIGNAL ;
    PORT
      LAYER M4 ;
        RECT  21.516 29.04 21.6 29.064 ;
    END
  END o[63]
  PIN o[64]
    DIRECTION OUTPUT ;
    USE SIGNAL ;
    PORT
      LAYER M4 ;
        RECT  21.516 6.864 21.6 6.888 ;
    END
  END o[64]
  PIN o[65]
    DIRECTION OUTPUT ;
    USE SIGNAL ;
    PORT
      LAYER M4 ;
        RECT  21.516 6.96 21.6 6.984 ;
    END
  END o[65]
  PIN o[66]
    DIRECTION OUTPUT ;
    USE SIGNAL ;
    PORT
      LAYER M4 ;
        RECT  21.516 7.056 21.6 7.08 ;
    END
  END o[66]
  PIN o[67]
    DIRECTION OUTPUT ;
    USE SIGNAL ;
    PORT
      LAYER M4 ;
        RECT  21.516 7.152 21.6 7.176 ;
    END
  END o[67]
  PIN o[68]
    DIRECTION OUTPUT ;
    USE SIGNAL ;
    PORT
      LAYER M4 ;
        RECT  21.516 7.248 21.6 7.272 ;
    END
  END o[68]
  PIN o[69]
    DIRECTION OUTPUT ;
    USE SIGNAL ;
    PORT
      LAYER M4 ;
        RECT  21.516 7.344 21.6 7.368 ;
    END
  END o[69]
  PIN o[6]
    DIRECTION OUTPUT ;
    USE SIGNAL ;
    PORT
      LAYER M4 ;
        RECT  21.516 10.512 21.6 10.536 ;
    END
  END o[6]
  PIN o[70]
    DIRECTION OUTPUT ;
    USE SIGNAL ;
    PORT
      LAYER M4 ;
        RECT  21.516 7.44 21.6 7.464 ;
    END
  END o[70]
  PIN o[71]
    DIRECTION OUTPUT ;
    USE SIGNAL ;
    PORT
      LAYER M4 ;
        RECT  21.516 7.536 21.6 7.56 ;
    END
  END o[71]
  PIN o[72]
    DIRECTION OUTPUT ;
    USE SIGNAL ;
    PORT
      LAYER M4 ;
        RECT  21.516 7.632 21.6 7.656 ;
    END
  END o[72]
  PIN o[73]
    DIRECTION OUTPUT ;
    USE SIGNAL ;
    PORT
      LAYER M4 ;
        RECT  21.516 7.728 21.6 7.752 ;
    END
  END o[73]
  PIN o[74]
    DIRECTION OUTPUT ;
    USE SIGNAL ;
    PORT
      LAYER M4 ;
        RECT  21.516 7.824 21.6 7.848 ;
    END
  END o[74]
  PIN o[75]
    DIRECTION OUTPUT ;
    USE SIGNAL ;
    PORT
      LAYER M4 ;
        RECT  21.516 7.92 21.6 7.944 ;
    END
  END o[75]
  PIN o[76]
    DIRECTION OUTPUT ;
    USE SIGNAL ;
    PORT
      LAYER M4 ;
        RECT  21.516 8.016 21.6 8.04 ;
    END
  END o[76]
  PIN o[77]
    DIRECTION OUTPUT ;
    USE SIGNAL ;
    PORT
      LAYER M4 ;
        RECT  21.516 8.112 21.6 8.136 ;
    END
  END o[77]
  PIN o[78]
    DIRECTION OUTPUT ;
    USE SIGNAL ;
    PORT
      LAYER M4 ;
        RECT  21.516 8.208 21.6 8.232 ;
    END
  END o[78]
  PIN o[79]
    DIRECTION OUTPUT ;
    USE SIGNAL ;
    PORT
      LAYER M4 ;
        RECT  21.516 8.304 21.6 8.328 ;
    END
  END o[79]
  PIN o[7]
    DIRECTION OUTPUT ;
    USE SIGNAL ;
    PORT
      LAYER M4 ;
        RECT  21.516 10.608 21.6 10.632 ;
    END
  END o[7]
  PIN o[80]
    DIRECTION OUTPUT ;
    USE SIGNAL ;
    PORT
      LAYER M4 ;
        RECT  21.516 8.4 21.6 8.424 ;
    END
  END o[80]
  PIN o[81]
    DIRECTION OUTPUT ;
    USE SIGNAL ;
    PORT
      LAYER M4 ;
        RECT  21.516 8.496 21.6 8.52 ;
    END
  END o[81]
  PIN o[82]
    DIRECTION OUTPUT ;
    USE SIGNAL ;
    PORT
      LAYER M4 ;
        RECT  21.516 8.592 21.6 8.616 ;
    END
  END o[82]
  PIN o[83]
    DIRECTION OUTPUT ;
    USE SIGNAL ;
    PORT
      LAYER M4 ;
        RECT  21.516 8.688 21.6 8.712 ;
    END
  END o[83]
  PIN o[84]
    DIRECTION OUTPUT ;
    USE SIGNAL ;
    PORT
      LAYER M4 ;
        RECT  21.516 8.784 21.6 8.808 ;
    END
  END o[84]
  PIN o[85]
    DIRECTION OUTPUT ;
    USE SIGNAL ;
    PORT
      LAYER M4 ;
        RECT  21.516 8.88 21.6 8.904 ;
    END
  END o[85]
  PIN o[86]
    DIRECTION OUTPUT ;
    USE SIGNAL ;
    PORT
      LAYER M4 ;
        RECT  21.516 8.976 21.6 9 ;
    END
  END o[86]
  PIN o[87]
    DIRECTION OUTPUT ;
    USE SIGNAL ;
    PORT
      LAYER M4 ;
        RECT  21.516 9.072 21.6 9.096 ;
    END
  END o[87]
  PIN o[88]
    DIRECTION OUTPUT ;
    USE SIGNAL ;
    PORT
      LAYER M4 ;
        RECT  21.516 9.168 21.6 9.192 ;
    END
  END o[88]
  PIN o[89]
    DIRECTION OUTPUT ;
    USE SIGNAL ;
    PORT
      LAYER M4 ;
        RECT  21.516 9.264 21.6 9.288 ;
    END
  END o[89]
  PIN o[8]
    DIRECTION OUTPUT ;
    USE SIGNAL ;
    PORT
      LAYER M4 ;
        RECT  21.516 10.704 21.6 10.728 ;
    END
  END o[8]
  PIN o[90]
    DIRECTION OUTPUT ;
    USE SIGNAL ;
    PORT
      LAYER M4 ;
        RECT  21.516 9.36 21.6 9.384 ;
    END
  END o[90]
  PIN o[91]
    DIRECTION OUTPUT ;
    USE SIGNAL ;
    PORT
      LAYER M4 ;
        RECT  21.516 9.456 21.6 9.48 ;
    END
  END o[91]
  PIN o[92]
    DIRECTION OUTPUT ;
    USE SIGNAL ;
    PORT
      LAYER M4 ;
        RECT  21.516 9.552 21.6 9.576 ;
    END
  END o[92]
  PIN o[93]
    DIRECTION OUTPUT ;
    USE SIGNAL ;
    PORT
      LAYER M4 ;
        RECT  21.516 9.648 21.6 9.672 ;
    END
  END o[93]
  PIN o[94]
    DIRECTION OUTPUT ;
    USE SIGNAL ;
    PORT
      LAYER M4 ;
        RECT  21.516 9.744 21.6 9.768 ;
    END
  END o[94]
  PIN o[95]
    DIRECTION OUTPUT ;
    USE SIGNAL ;
    PORT
      LAYER M4 ;
        RECT  21.516 9.84 21.6 9.864 ;
    END
  END o[95]
  PIN o[96]
    DIRECTION OUTPUT ;
    USE SIGNAL ;
    PORT
      LAYER M4 ;
        RECT  21.516 13.008 21.6 13.032 ;
    END
  END o[96]
  PIN o[97]
    DIRECTION OUTPUT ;
    USE SIGNAL ;
    PORT
      LAYER M4 ;
        RECT  21.516 13.104 21.6 13.128 ;
    END
  END o[97]
  PIN o[98]
    DIRECTION OUTPUT ;
    USE SIGNAL ;
    PORT
      LAYER M4 ;
        RECT  21.516 13.2 21.6 13.224 ;
    END
  END o[98]
  PIN o[99]
    DIRECTION OUTPUT ;
    USE SIGNAL ;
    PORT
      LAYER M4 ;
        RECT  21.516 13.296 21.6 13.32 ;
    END
  END o[99]
  PIN o[9]
    DIRECTION OUTPUT ;
    USE SIGNAL ;
    PORT
      LAYER M4 ;
        RECT  21.516 10.8 21.6 10.824 ;
    END
  END o[9]
  PIN rfi
    DIRECTION INPUT ;
    USE SIGNAL ;
    PORT
      LAYER M4 ;
        RECT  0 11.472 0.084 11.496 ;
    END
  END rfi
  PIN rfo
    DIRECTION OUTPUT ;
    USE SIGNAL ;
    PORT
      LAYER M4 ;
        RECT  21.516 24.528 21.6 24.552 ;
    END
  END rfo
  PIN rs
    DIRECTION INPUT ;
    USE SIGNAL ;
    PORT
      LAYER M5 ;
        RECT  13.104 0 13.128 0.084 ;
    END
  END rs
  PIN rso
    DIRECTION OUTPUT ;
    USE SIGNAL ;
    PORT
      LAYER M4 ;
        RECT  21.516 24.624 21.6 24.648 ;
    END
  END rso
  PIN VDD
    DIRECTION INOUT ;
    USE POWER ;
    PORT
      LAYER M5 ;
        RECT  18.792 2.151 18.912 32.409 ;
        RECT  16.092 2.151 16.212 32.409 ;
        RECT  13.392 2.151 13.512 32.409 ;
        RECT  10.692 2.151 10.812 32.409 ;
        RECT  7.992 2.151 8.112 32.409 ;
        RECT  5.292 2.151 5.412 32.409 ;
        RECT  2.592 2.151 2.712 32.409 ;
    END
  END VDD
  PIN VSS
    DIRECTION INOUT ;
    USE GROUND ;
    PORT
      LAYER M5 ;
        RECT  18.6 2.137 18.72 32.423 ;
        RECT  15.9 2.137 16.02 32.423 ;
        RECT  13.2 2.137 13.32 32.423 ;
        RECT  10.5 2.137 10.62 32.423 ;
        RECT  7.8 2.137 7.92 32.423 ;
        RECT  5.1 2.137 5.22 32.423 ;
        RECT  2.4 2.137 2.52 32.423 ;
    END
  END VSS
  OBS
    LAYER RVTN ;
     RECT  2.16 2.16 19.44 2.295 ;
     RECT  2.16 2.565 19.44 2.835 ;
     RECT  2.16 3.105 19.44 3.375 ;
     RECT  2.16 3.645 19.44 3.915 ;
     RECT  2.16 4.185 19.44 4.455 ;
     RECT  2.16 4.725 19.44 4.995 ;
     RECT  2.16 5.265 19.44 5.535 ;
     RECT  2.16 5.805 19.44 6.075 ;
     RECT  2.16 6.345 19.44 6.615 ;
     RECT  2.16 6.885 19.44 7.155 ;
     RECT  2.16 7.425 19.44 7.695 ;
     RECT  2.16 7.965 19.44 8.235 ;
     RECT  2.16 8.505 19.44 8.775 ;
     RECT  2.16 9.045 19.44 9.315 ;
     RECT  2.16 9.585 19.44 9.855 ;
     RECT  2.16 10.125 19.44 10.395 ;
     RECT  2.16 10.665 19.44 10.935 ;
     RECT  2.16 11.205 19.44 11.475 ;
     RECT  2.16 11.745 19.44 12.015 ;
     RECT  2.16 12.285 19.44 12.555 ;
     RECT  2.16 12.825 19.44 13.095 ;
     RECT  2.16 13.365 19.44 13.635 ;
     RECT  2.16 13.905 19.44 14.175 ;
     RECT  2.16 14.445 19.44 14.715 ;
     RECT  2.16 14.985 19.44 15.255 ;
     RECT  2.16 15.525 19.44 15.795 ;
     RECT  2.16 16.065 19.44 16.335 ;
     RECT  2.16 16.605 19.44 16.875 ;
     RECT  2.16 17.145 19.44 17.415 ;
     RECT  2.16 17.685 19.44 17.955 ;
     RECT  2.16 18.225 19.44 18.495 ;
     RECT  2.16 18.765 19.44 19.035 ;
     RECT  2.16 19.305 19.44 19.575 ;
     RECT  2.16 19.845 19.44 20.115 ;
     RECT  2.16 20.385 19.44 20.655 ;
     RECT  2.16 20.925 19.44 21.195 ;
     RECT  2.16 21.465 19.44 21.735 ;
     RECT  2.16 22.005 19.44 22.275 ;
     RECT  2.16 22.545 19.44 22.815 ;
     RECT  2.16 23.085 19.44 23.355 ;
     RECT  2.16 23.625 19.44 23.895 ;
     RECT  2.16 24.165 19.44 24.435 ;
     RECT  2.16 24.705 19.44 24.975 ;
     RECT  2.16 25.245 19.44 25.515 ;
     RECT  2.16 25.785 19.44 26.055 ;
     RECT  2.16 26.325 19.44 26.595 ;
     RECT  2.16 26.865 19.44 27.135 ;
     RECT  2.16 27.405 19.44 27.675 ;
     RECT  2.16 27.945 19.44 28.215 ;
     RECT  2.16 28.485 19.44 28.755 ;
     RECT  2.16 29.025 19.44 29.295 ;
     RECT  2.16 29.565 19.44 29.835 ;
     RECT  2.16 30.105 19.44 30.375 ;
     RECT  2.16 30.645 19.44 30.915 ;
     RECT  2.16 31.185 19.44 31.455 ;
     RECT  2.16 31.725 19.44 31.995 ;
     RECT  2.16 32.265 19.44 32.4 ;
    LAYER RVTP ;
     RECT  2.16 2.295 19.44 2.565 ;
     RECT  2.16 2.835 19.44 3.105 ;
     RECT  2.16 3.375 19.44 3.645 ;
     RECT  2.16 3.915 19.44 4.185 ;
     RECT  2.16 4.455 19.44 4.725 ;
     RECT  2.16 4.995 19.44 5.265 ;
     RECT  2.16 5.535 19.44 5.805 ;
     RECT  2.16 6.075 19.44 6.345 ;
     RECT  2.16 6.615 19.44 6.885 ;
     RECT  2.16 7.155 19.44 7.425 ;
     RECT  2.16 7.695 19.44 7.965 ;
     RECT  2.16 8.235 19.44 8.505 ;
     RECT  2.16 8.775 19.44 9.045 ;
     RECT  2.16 9.315 19.44 9.585 ;
     RECT  2.16 9.855 19.44 10.125 ;
     RECT  2.16 10.395 19.44 10.665 ;
     RECT  2.16 10.935 19.44 11.205 ;
     RECT  2.16 11.475 19.44 11.745 ;
     RECT  2.16 12.015 19.44 12.285 ;
     RECT  2.16 12.555 19.44 12.825 ;
     RECT  2.16 13.095 19.44 13.365 ;
     RECT  2.16 13.635 19.44 13.905 ;
     RECT  2.16 14.175 19.44 14.445 ;
     RECT  2.16 14.715 19.44 14.985 ;
     RECT  2.16 15.255 19.44 15.525 ;
     RECT  2.16 15.795 19.44 16.065 ;
     RECT  2.16 16.335 19.44 16.605 ;
     RECT  2.16 16.875 19.44 17.145 ;
     RECT  2.16 17.415 19.44 17.685 ;
     RECT  2.16 17.955 19.44 18.225 ;
     RECT  2.16 18.495 19.44 18.765 ;
     RECT  2.16 19.035 19.44 19.305 ;
     RECT  2.16 19.575 19.44 19.845 ;
     RECT  2.16 20.115 19.44 20.385 ;
     RECT  2.16 20.655 19.44 20.925 ;
     RECT  2.16 21.195 19.44 21.465 ;
     RECT  2.16 21.735 19.44 22.005 ;
     RECT  2.16 22.275 19.44 22.545 ;
     RECT  2.16 22.815 19.44 23.085 ;
     RECT  2.16 23.355 19.44 23.625 ;
     RECT  2.16 23.895 19.44 24.165 ;
     RECT  2.16 24.435 19.44 24.705 ;
     RECT  2.16 24.975 19.44 25.245 ;
     RECT  2.16 25.515 19.44 25.785 ;
     RECT  2.16 26.055 19.44 26.325 ;
     RECT  2.16 26.595 19.44 26.865 ;
     RECT  2.16 27.135 19.44 27.405 ;
     RECT  2.16 27.675 19.44 27.945 ;
     RECT  2.16 28.215 19.44 28.485 ;
     RECT  2.16 28.755 19.44 29.025 ;
     RECT  2.16 29.295 19.44 29.565 ;
     RECT  2.16 29.835 19.44 30.105 ;
     RECT  2.16 30.375 19.44 30.645 ;
     RECT  2.16 30.915 19.44 31.185 ;
     RECT  2.16 31.455 19.44 31.725 ;
     RECT  2.16 31.995 19.44 32.265 ;
    LAYER M1 ;
     RECT  2.16 2.151 19.44 32.409 ;
    LAYER M2 ;
     RECT  0.103 29.961 0.175 30.6 ;
     RECT  0.139 18.774 0.239 18.792 ;
     RECT  0.175 29.538 0.239 30.6 ;
     RECT  0.247 28.386 0.347 28.404 ;
     RECT  0.239 29.538 0.347 29.556 ;
     RECT  0.283 12.726 0.383 12.744 ;
     RECT  0.239 30.42 0.419 30.6 ;
     RECT  0.419 30.582 0.427 30.6 ;
     RECT  0.103 6.39 0.455 6.408 ;
     RECT  0.427 30.582 0.455 31.248 ;
     RECT  0.455 31.23 0.707 31.248 ;
     RECT  1.147 17.082 2.16 17.1 ;
     RECT  2.16 2.151 2.875 32.409 ;
     RECT  2.875 2.106 3.407 32.409 ;
     RECT  3.407 2.151 4.315 32.409 ;
     RECT  4.315 2.106 4.991 32.409 ;
     RECT  4.991 2.151 8.491 32.409 ;
     RECT  8.491 2.034 10.463 32.409 ;
     RECT  10.463 2.07 10.751 32.409 ;
     RECT  10.751 2.106 10.967 32.409 ;
     RECT  10.967 2.151 12.415 32.409 ;
     RECT  12.415 1.692 13.099 32.409 ;
     RECT  13.099 1.692 13.415 32.454 ;
     RECT  13.415 1.692 15.331 32.409 ;
     RECT  15.331 1.692 18.599 32.49 ;
     RECT  18.599 1.692 18.959 32.409 ;
     RECT  18.959 2.106 19.44 32.409 ;
     RECT  19.44 4.806 19.751 7.344 ;
     RECT  19.44 13.644 19.859 15.624 ;
     RECT  19.859 13.644 19.895 14.859 ;
     RECT  19.44 16.686 19.895 19.368 ;
     RECT  19.44 8.406 19.931 9.072 ;
     RECT  19.44 11.916 19.931 12.744 ;
     RECT  19.859 15.606 19.931 15.624 ;
     RECT  19.44 20.196 19.931 22.878 ;
     RECT  19.44 28.296 19.931 29.628 ;
     RECT  19.931 12.366 19.967 12.744 ;
     RECT  19.931 28.386 19.967 29.628 ;
     RECT  19.44 30.456 19.967 32.022 ;
     RECT  19.895 17.694 20.435 19.368 ;
     RECT  19.44 2.106 20.471 3.942 ;
     RECT  19.931 8.406 20.507 8.874 ;
     RECT  19.44 10.026 20.507 10.044 ;
     RECT  19.931 21.096 20.507 21.492 ;
     RECT  19.44 26.37 20.507 26.964 ;
     RECT  19.967 28.386 20.507 28.584 ;
     RECT  20.507 8.784 20.543 8.874 ;
     RECT  19.967 12.726 20.543 12.744 ;
     RECT  19.895 16.686 20.543 16.704 ;
     RECT  19.44 23.634 20.543 24.624 ;
     RECT  20.507 26.604 20.543 26.964 ;
     RECT  20.507 28.566 20.543 28.584 ;
     RECT  20.543 8.784 20.579 8.802 ;
     RECT  20.543 26.604 20.579 26.622 ;
     RECT  19.751 5.742 21.163 7.344 ;
     RECT  19.967 29.574 21.199 29.628 ;
     RECT  19.895 13.644 21.307 14.238 ;
     RECT  21.307 9.522 21.343 9.54 ;
     RECT  21.271 10.674 21.343 10.692 ;
     RECT  21.235 11.682 21.343 12.348 ;
     RECT  20.471 2.106 21.371 3.744 ;
     RECT  21.199 29.538 21.371 29.628 ;
     RECT  21.343 9.522 21.379 9.882 ;
     RECT  21.343 10.674 21.379 12.348 ;
     RECT  21.371 2.106 21.407 3.168 ;
     RECT  21.307 13.644 21.407 14.67 ;
     RECT  20.435 19.35 21.407 19.368 ;
     RECT  20.507 21.474 21.407 21.492 ;
     RECT  21.379 9.522 21.415 12.348 ;
     RECT  21.407 2.376 21.443 3.168 ;
     RECT  21.163 5.742 21.443 7.686 ;
     RECT  19.44 25.416 21.443 25.614 ;
     RECT  21.443 7.326 21.479 7.686 ;
     RECT  21.343 8.478 21.479 8.496 ;
     RECT  21.415 9.36 21.479 12.348 ;
     RECT  19.931 22.626 21.479 22.878 ;
     RECT  20.543 23.634 21.479 23.688 ;
     RECT  20.543 24.516 21.479 24.624 ;
     RECT  21.343 28.764 21.479 28.782 ;
     RECT  19.967 31.194 21.479 32.022 ;
     RECT  21.443 2.376 21.515 2.754 ;
     RECT  19.751 4.806 21.515 4.824 ;
     RECT  21.443 6.048 21.515 6.444 ;
     RECT  21.479 9.36 21.515 9.378 ;
     RECT  21.479 10.332 21.515 12.348 ;
     RECT  21.407 13.644 21.515 14.238 ;
     RECT  21.415 14.994 21.515 15.012 ;
     RECT  21.415 16.308 21.515 16.326 ;
     RECT  20.435 17.694 21.515 18.522 ;
     RECT  19.931 20.196 21.515 20.214 ;
     RECT  21.479 22.626 21.515 22.644 ;
     RECT  21.479 23.67 21.515 23.688 ;
     RECT  21.479 24.606 21.515 24.624 ;
     RECT  21.443 25.596 21.515 25.614 ;
     RECT  21.371 29.61 21.515 29.628 ;
     RECT  21.479 31.194 21.515 31.212 ;
     RECT  21.479 32.004 21.515 32.022 ;
    LAYER M3 ;
     RECT  15.876 0.715 15.894 1.099 ;
     RECT  21.492 0.811 21.51 1.195 ;
     RECT  21.456 1.195 21.51 1.483 ;
     RECT  13.032 0.907 13.05 1.579 ;
     RECT  21.42 1.483 21.51 1.675 ;
     RECT  12.492 1.579 13.05 1.687 ;
     RECT  19.656 1.387 19.674 1.687 ;
     RECT  15.516 1.099 15.894 1.723 ;
     RECT  21.384 1.675 21.51 1.723 ;
     RECT  12.42 1.687 13.05 1.771 ;
     RECT  17.676 1.771 17.694 1.993 ;
     RECT  8.82 2.011 8.838 2.029 ;
     RECT  10.224 1.915 10.242 2.029 ;
     RECT  10.224 2.029 10.458 2.059 ;
     RECT  14.832 1.723 16.866 2.059 ;
     RECT  8.496 2.029 8.838 2.065 ;
     RECT  9.936 2.059 10.458 2.065 ;
     RECT  8.496 2.065 10.746 2.101 ;
     RECT  14.832 2.059 16.938 2.101 ;
     RECT  2.88 2.101 3.402 2.143 ;
     RECT  4.32 2.101 4.986 2.143 ;
     RECT  7.38 2.059 7.398 2.143 ;
     RECT  8.496 2.101 10.962 2.143 ;
     RECT  18.936 1.687 19.674 2.143 ;
     RECT  2.415 2.143 3.402 2.191 ;
     RECT  4.32 2.143 5.205 2.191 ;
     RECT  12.42 1.771 13.374 2.191 ;
     RECT  14.112 2.101 16.938 2.191 ;
     RECT  17.676 1.993 17.766 2.191 ;
     RECT  7.38 2.143 10.962 2.251 ;
     RECT  12.42 2.191 17.766 2.251 ;
     RECT  18.615 2.143 19.674 2.251 ;
     RECT  12.42 2.251 19.674 2.263 ;
     RECT  11.988 2.263 19.674 2.299 ;
     RECT  2.415 2.191 5.526 2.335 ;
     RECT  7.2 2.251 11.178 2.347 ;
     RECT  11.952 2.299 19.674 2.347 ;
     RECT  7.2 2.347 19.674 2.443 ;
     RECT  21.276 1.723 21.51 2.491 ;
     RECT  6.732 2.443 19.674 2.497 ;
     RECT  6.3 2.497 19.674 2.635 ;
     RECT  2.304 2.335 5.526 2.641 ;
     RECT  6.3 2.635 19.746 2.641 ;
     RECT  0.144 2.491 0.162 2.669 ;
     RECT  21.24 2.491 21.51 2.759 ;
     RECT  21.276 2.759 21.51 2.861 ;
     RECT  21.348 2.861 21.51 3.749 ;
     RECT  2.304 2.641 19.746 3.919 ;
     RECT  20.484 2.923 20.502 3.919 ;
     RECT  0.324 3.979 0.342 4.205 ;
     RECT  21.492 3.749 21.51 4.555 ;
     RECT  21.42 4.555 21.51 4.651 ;
     RECT  0.18 4.411 0.198 4.685 ;
     RECT  2.304 3.919 20.502 4.747 ;
     RECT  21.276 4.651 21.51 4.747 ;
     RECT  2.304 4.747 21.51 4.829 ;
     RECT  2.304 4.829 21.438 4.877 ;
     RECT  2.304 4.877 20.502 5.197 ;
     RECT  2.268 5.197 20.502 5.309 ;
     RECT  2.268 5.309 20.466 5.323 ;
     RECT  2.232 5.323 20.466 5.495 ;
     RECT  0.324 5.419 0.342 5.549 ;
     RECT  2.304 5.495 20.466 5.639 ;
     RECT  20.376 5.639 20.466 5.873 ;
     RECT  20.448 5.873 20.466 5.909 ;
     RECT  21.384 4.877 21.438 5.995 ;
     RECT  21.384 5.995 21.51 6.091 ;
     RECT  21.312 6.091 21.51 6.221 ;
     RECT  0.144 5.707 0.162 6.379 ;
     RECT  0.108 6.379 0.45 6.413 ;
     RECT  21.42 6.221 21.51 6.449 ;
     RECT  21.42 6.449 21.474 6.955 ;
     RECT  21.384 6.955 21.474 7.243 ;
     RECT  21.312 7.243 21.474 7.435 ;
     RECT  2.304 5.639 19.278 7.465 ;
     RECT  2.232 7.465 19.278 7.501 ;
     RECT  2.232 7.501 19.314 7.517 ;
     RECT  2.304 7.517 19.314 7.619 ;
     RECT  20.484 6.475 20.502 7.663 ;
     RECT  21.24 7.435 21.474 7.663 ;
     RECT  20.484 7.663 21.474 7.691 ;
     RECT  20.484 7.691 21.402 7.757 ;
     RECT  0.144 6.413 0.306 7.771 ;
     RECT  0.144 7.771 0.342 7.949 ;
     RECT  0.144 7.949 0.162 8.189 ;
     RECT  21.276 7.757 21.402 8.237 ;
     RECT  21.312 8.237 21.402 8.473 ;
     RECT  21.312 8.473 21.474 8.525 ;
     RECT  2.304 7.619 19.278 8.539 ;
     RECT  2.304 8.539 19.314 8.683 ;
     RECT  20.484 7.757 20.502 8.779 ;
     RECT  2.268 8.683 19.314 8.875 ;
     RECT  20.484 8.779 20.574 8.875 ;
     RECT  2.268 8.875 20.574 9.005 ;
     RECT  2.268 9.005 20.502 9.275 ;
     RECT  21.42 8.525 21.438 9.355 ;
     RECT  21.312 9.355 21.51 9.389 ;
     RECT  21.312 9.389 21.474 9.451 ;
     RECT  0.144 9.979 0.162 10.027 ;
     RECT  2.304 9.275 20.502 10.049 ;
     RECT  0.144 10.027 0.342 10.157 ;
     RECT  0.252 10.157 0.27 10.253 ;
     RECT  21.276 9.451 21.474 10.315 ;
     RECT  21.276 10.315 21.51 10.733 ;
     RECT  0.144 11.467 0.162 11.645 ;
     RECT  21.312 10.733 21.51 11.677 ;
     RECT  2.304 10.049 19.926 12.361 ;
     RECT  21.24 11.677 21.51 12.365 ;
     RECT  0.144 12.379 0.162 12.557 ;
     RECT  2.304 12.361 19.962 12.557 ;
     RECT  2.304 12.557 19.386 12.653 ;
     RECT  21.24 12.365 21.366 12.715 ;
     RECT  0.288 12.715 0.306 12.721 ;
     RECT  21.204 12.715 21.366 12.721 ;
     RECT  0.288 12.721 0.378 12.749 ;
     RECT  2.304 12.653 19.314 12.763 ;
     RECT  0.36 12.749 0.378 12.845 ;
     RECT  20.52 12.721 21.366 12.845 ;
     RECT  21.276 12.845 21.366 13.037 ;
     RECT  2.232 12.763 19.314 13.289 ;
     RECT  2.232 13.289 19.242 13.469 ;
     RECT  21.42 13.195 21.438 13.483 ;
     RECT  0.144 13.579 0.162 13.675 ;
     RECT  0.144 13.675 0.378 13.805 ;
     RECT  20.52 12.845 20.538 13.805 ;
     RECT  0.144 13.805 0.306 13.949 ;
     RECT  21.42 13.483 21.51 14.059 ;
     RECT  0.144 13.949 0.234 14.141 ;
     RECT  2.304 13.469 19.242 14.143 ;
     RECT  21.348 14.059 21.51 14.347 ;
     RECT  0.144 14.141 0.198 14.539 ;
     RECT  0.108 14.539 0.198 14.621 ;
     RECT  0.108 14.621 0.126 14.669 ;
     RECT  21.276 14.347 21.51 14.669 ;
     RECT  2.304 14.143 19.89 14.827 ;
     RECT  21.312 14.669 21.51 15.053 ;
     RECT  2.304 14.827 19.926 15.067 ;
     RECT  21.312 15.053 21.438 15.245 ;
     RECT  2.304 15.067 20.502 15.565 ;
     RECT  2.268 15.565 20.502 15.725 ;
     RECT  21.348 15.245 21.438 15.917 ;
     RECT  21.384 15.917 21.438 16.267 ;
     RECT  21.384 16.267 21.51 16.331 ;
     RECT  2.304 15.725 20.502 16.537 ;
     RECT  2.268 16.537 20.502 16.681 ;
     RECT  2.268 16.681 20.538 16.877 ;
     RECT  2.268 16.877 20.502 17.069 ;
     RECT  21.384 16.331 21.438 17.069 ;
     RECT  21.42 17.069 21.438 17.131 ;
     RECT  1.152 17.077 1.17 17.179 ;
     RECT  1.152 17.179 1.314 17.309 ;
     RECT  2.268 17.069 19.422 17.309 ;
     RECT  1.296 17.309 1.314 17.357 ;
     RECT  21.42 17.131 21.51 17.803 ;
     RECT  21.276 17.803 21.51 17.923 ;
     RECT  0.144 17.131 0.162 17.995 ;
     RECT  21.24 17.923 21.51 18.029 ;
     RECT  2.304 17.309 19.422 18.031 ;
     RECT  20.448 17.069 20.502 18.031 ;
     RECT  2.304 18.031 20.502 18.125 ;
     RECT  21.312 18.029 21.51 18.221 ;
     RECT  0.144 17.995 0.558 18.365 ;
     RECT  21.348 18.221 21.51 18.557 ;
     RECT  2.304 18.125 19.458 18.893 ;
     RECT  20.448 18.125 20.502 18.955 ;
     RECT  20.412 18.955 20.502 18.995 ;
     RECT  0.144 18.365 0.342 19.037 ;
     RECT  2.304 18.893 19.422 19.277 ;
     RECT  21.492 18.557 21.51 19.345 ;
     RECT  2.304 19.277 19.314 19.651 ;
     RECT  2.268 19.651 19.314 19.661 ;
     RECT  2.268 19.661 18.99 19.885 ;
     RECT  20.448 18.995 20.502 19.901 ;
     RECT  2.232 19.885 18.99 19.949 ;
     RECT  0.216 19.037 0.342 20.107 ;
     RECT  0.144 20.107 0.342 20.141 ;
     RECT  21.384 19.345 21.51 20.219 ;
     RECT  0.144 20.141 0.162 20.285 ;
     RECT  21.384 20.219 21.402 20.285 ;
     RECT  2.268 19.949 18.99 20.395 ;
     RECT  21.276 20.299 21.366 20.429 ;
     RECT  21.348 20.429 21.366 20.525 ;
     RECT  20.448 19.901 20.466 20.683 ;
     RECT  2.268 20.395 19.386 20.779 ;
     RECT  20.376 20.683 20.502 20.779 ;
     RECT  2.268 20.779 20.502 21.005 ;
     RECT  19.908 21.005 20.502 21.119 ;
     RECT  21.42 21.211 21.438 21.259 ;
     RECT  21.42 21.259 21.51 21.469 ;
     RECT  21.384 21.469 21.51 21.643 ;
     RECT  21.276 21.643 21.51 21.835 ;
     RECT  0.252 21.739 0.27 21.931 ;
     RECT  1.152 21.835 1.17 21.965 ;
     RECT  2.268 21.005 19.17 22.199 ;
     RECT  0.252 21.931 0.342 22.219 ;
     RECT  21.204 21.835 21.51 22.541 ;
     RECT  21.276 22.541 21.51 22.637 ;
     RECT  0.18 22.219 0.342 22.891 ;
     RECT  0.144 22.891 0.342 23.069 ;
     RECT  2.268 22.199 19.134 23.125 ;
     RECT  19.908 21.119 19.926 23.125 ;
     RECT  0.216 23.069 0.342 23.261 ;
     RECT  0.324 23.261 0.342 23.309 ;
     RECT  21.312 22.637 21.51 23.309 ;
     RECT  2.268 23.125 19.926 23.585 ;
     RECT  2.304 23.585 19.926 23.729 ;
     RECT  20.484 23.755 20.502 23.819 ;
     RECT  21.42 23.309 21.51 24.043 ;
     RECT  21.276 24.043 21.51 24.173 ;
     RECT  20.52 23.947 20.538 24.233 ;
     RECT  2.304 23.729 19.386 24.269 ;
     RECT  1.152 24.139 1.17 24.461 ;
     RECT  21.348 24.173 21.51 24.629 ;
     RECT  21.348 24.629 21.438 24.701 ;
     RECT  21.42 24.701 21.438 25.439 ;
     RECT  0.144 25.099 0.162 25.531 ;
     RECT  0.144 25.531 0.378 25.709 ;
     RECT  2.304 24.269 19.314 25.817 ;
     RECT  0.144 25.709 0.342 26.381 ;
     RECT  21.492 25.591 21.51 26.443 ;
     RECT  2.304 25.817 19.098 26.491 ;
     RECT  0.144 26.381 0.162 26.525 ;
     RECT  20.484 26.347 20.502 26.599 ;
     RECT  2.268 26.491 19.098 26.635 ;
     RECT  20.484 26.599 20.574 26.635 ;
     RECT  21.42 26.443 21.51 26.765 ;
     RECT  2.268 26.635 20.574 27.059 ;
     RECT  2.268 27.059 11.79 27.167 ;
     RECT  12.564 27.059 20.574 27.203 ;
     RECT  12.708 27.203 20.574 27.245 ;
     RECT  0.324 27.115 0.342 27.403 ;
     RECT  0.252 27.403 0.342 27.499 ;
     RECT  0.144 27.499 0.342 27.677 ;
     RECT  13.14 27.245 20.574 27.725 ;
     RECT  21.42 26.765 21.438 27.787 ;
     RECT  2.304 27.167 11.79 27.841 ;
     RECT  13.14 27.725 20.502 27.869 ;
     RECT  21.276 27.787 21.438 27.917 ;
     RECT  2.304 27.841 11.826 27.985 ;
     RECT  2.268 27.985 12.33 28.139 ;
     RECT  0.252 27.677 0.342 28.363 ;
     RECT  0.252 28.363 0.378 28.409 ;
     RECT  13.176 27.869 20.502 28.561 ;
     RECT  13.176 28.561 20.538 28.651 ;
     RECT  21.348 27.917 21.438 28.651 ;
     RECT  2.268 28.139 12.258 28.715 ;
     RECT  21.276 28.651 21.438 28.747 ;
     RECT  13.104 28.651 20.538 28.877 ;
     RECT  13.104 28.877 19.962 29.117 ;
     RECT  0.324 28.409 0.378 29.179 ;
     RECT  0.216 29.179 0.378 29.227 ;
     RECT  2.304 28.715 12.258 29.263 ;
     RECT  13.104 29.117 19.314 29.263 ;
     RECT  2.304 29.263 19.314 29.309 ;
     RECT  0.144 29.227 0.378 29.323 ;
     RECT  21.276 28.747 21.474 29.323 ;
     RECT  21.276 29.323 21.51 29.419 ;
     RECT  21.204 29.419 21.51 29.633 ;
     RECT  21.204 29.633 21.438 29.645 ;
     RECT  2.304 29.309 19.062 29.707 ;
     RECT  2.232 29.707 19.062 29.759 ;
     RECT  0.144 29.323 0.414 29.899 ;
     RECT  0.144 29.899 0.702 29.956 ;
     RECT  2.304 29.759 19.062 30.181 ;
     RECT  2.304 30.181 19.134 30.415 ;
     RECT  2.304 30.415 19.314 30.451 ;
     RECT  0.108 29.956 0.702 30.605 ;
     RECT  21.276 29.645 21.438 30.605 ;
     RECT  2.304 30.451 19.962 30.701 ;
     RECT  21.42 30.605 21.438 30.859 ;
     RECT  21.42 30.859 21.51 31.229 ;
     RECT  0.144 30.605 0.702 31.253 ;
     RECT  2.304 30.701 19.314 31.261 ;
     RECT  0.144 31.253 0.558 31.325 ;
     RECT  2.232 31.261 19.314 31.325 ;
     RECT  20.484 31.339 20.502 31.435 ;
     RECT  0.288 31.325 0.558 31.469 ;
     RECT  2.304 31.325 19.314 31.531 ;
     RECT  0.288 31.469 0.45 31.565 ;
     RECT  20.484 31.435 20.538 31.627 ;
     RECT  2.304 31.531 19.386 31.649 ;
     RECT  0.36 31.565 0.45 31.661 ;
     RECT  20.412 31.627 20.538 31.675 ;
     RECT  20.34 31.675 20.538 31.721 ;
     RECT  20.412 31.721 20.538 31.829 ;
     RECT  13.104 31.649 19.386 31.919 ;
     RECT  20.412 31.829 20.502 32.045 ;
     RECT  0.432 31.661 0.45 32.093 ;
     RECT  2.304 31.649 12.366 32.189 ;
     RECT  14.796 31.919 17.658 32.189 ;
     RECT  18.396 31.919 19.386 32.189 ;
     RECT  2.304 32.189 6.102 32.225 ;
     RECT  6.984 32.189 7.905 32.225 ;
     RECT  4.068 32.225 6.03 32.237 ;
     RECT  9.144 32.189 11.034 32.237 ;
     RECT  21.456 31.229 21.51 32.237 ;
     RECT  4.068 32.237 5.274 32.261 ;
     RECT  6.984 32.225 7.002 32.261 ;
     RECT  9.648 32.237 11.034 32.261 ;
     RECT  13.104 31.919 13.986 32.261 ;
     RECT  15.336 32.189 17.37 32.261 ;
     RECT  12.348 32.189 12.366 32.285 ;
     RECT  2.304 32.225 3.222 32.305 ;
     RECT  2.268 32.305 3.222 32.333 ;
     RECT  9.648 32.261 9.666 32.333 ;
     RECT  17.028 32.261 17.37 32.333 ;
     RECT  20.484 32.045 20.502 32.333 ;
     RECT  4.068 32.261 5.205 32.369 ;
     RECT  6.012 32.237 6.03 32.369 ;
     RECT  17.028 32.333 17.046 32.369 ;
     RECT  18.576 32.189 19.386 32.369 ;
     RECT  0.576 32.203 0.594 32.381 ;
     RECT  2.268 32.333 3.114 32.381 ;
     RECT  2.304 32.381 3.114 32.417 ;
     RECT  5.115 32.369 5.205 32.417 ;
     RECT  7.815 32.225 7.905 32.417 ;
     RECT  10.515 32.261 11.034 32.417 ;
     RECT  18.576 32.369 18.705 32.417 ;
     RECT  2.304 32.417 2.322 32.477 ;
     RECT  11.016 32.417 11.034 32.477 ;
     RECT  13.104 32.261 13.41 32.477 ;
     RECT  15.336 32.261 16.11 32.477 ;
     RECT  21.492 32.237 21.51 32.477 ;
     RECT  15.336 32.477 15.354 32.495 ;
     RECT  18.576 32.417 18.594 32.495 ;
     RECT  3.096 32.417 3.114 33.101 ;
    LAYER M4 ;
     RECT  0.06 2.352 0.133 8.424 ;
     RECT  0.133 2.352 0.181 8.568 ;
     RECT  0.06 9.936 0.181 33.768 ;
     RECT  0.181 2.352 1.139 33.768 ;
     RECT  1.139 2.352 2.408 33.096 ;
     RECT  2.408 2.148 2.512 33.096 ;
     RECT  2.512 2.256 3.125 33.096 ;
     RECT  3.125 2.256 3.233 32.328 ;
     RECT  3.233 2.256 3.443 32.088 ;
     RECT  3.443 2.256 3.541 32.04 ;
     RECT  3.541 2.064 4.453 32.04 ;
     RECT  4.453 2.064 4.597 32.232 ;
     RECT  4.597 2.016 5.108 32.232 ;
     RECT  5.108 2.016 5.212 32.412 ;
     RECT  5.212 2.016 5.789 32.232 ;
     RECT  5.789 2.016 6.113 32.04 ;
     RECT  6.113 2.016 7.808 31.992 ;
     RECT  7.808 2.016 7.912 32.412 ;
     RECT  7.912 2.016 8.104 32.142 ;
     RECT  8.104 2.016 9.133 32.136 ;
     RECT  9.133 2.016 9.637 32.232 ;
     RECT  9.637 1.968 10.213 32.328 ;
     RECT  10.213 1.92 10.508 32.328 ;
     RECT  10.508 1.92 11.005 32.412 ;
     RECT  11.005 1.92 11.845 32.472 ;
     RECT  11.845 1.824 12.481 32.472 ;
     RECT  12.481 1.584 13.021 32.472 ;
     RECT  13.021 0.912 15.865 32.472 ;
     RECT  15.865 0.72 19.325 32.472 ;
     RECT  19.325 0.72 21.409 24.696 ;
     RECT  21.409 0.72 21.491 24.744 ;
     RECT  19.325 26.064 21.521 32.472 ;
     RECT  21.491 0.72 21.564 24.648 ;
     RECT  21.521 26.064 21.564 32.136 ;
    LAYER M5 ;
     RECT  14.208 1.765 14.232 1.813 ;
     RECT  16.512 1.717 16.536 1.813 ;
     RECT  16.512 1.813 17.256 1.909 ;
     RECT  14.208 1.813 14.952 1.955 ;
     RECT  4.608 2.005 4.632 2.137 ;
     RECT  9.648 1.957 9.672 2.137 ;
     RECT  13.008 0.016 13.128 2.137 ;
     RECT  14.208 1.955 14.808 2.137 ;
     RECT  16.416 1.909 17.256 2.137 ;
     RECT  19.344 0.997 19.368 2.137 ;
     RECT  2.4 2.137 2.52 2.151 ;
     RECT  3.552 2.053 3.576 2.151 ;
     RECT  4.608 2.137 5.22 2.151 ;
     RECT  7.8 2.137 7.92 2.151 ;
     RECT  9.648 2.137 10.62 2.151 ;
     RECT  7.8 2.151 8.112 2.245 ;
     RECT  15.9 2.137 17.256 2.437 ;
     RECT  18.6 2.137 19.368 2.437 ;
     RECT  7.2 2.245 8.112 2.485 ;
     RECT  9.648 2.151 10.812 2.485 ;
     RECT  7.2 2.485 10.812 2.533 ;
     RECT  11.856 1.813 11.88 2.533 ;
     RECT  7.2 2.533 11.88 2.677 ;
     RECT  0.144 2.437 0.168 2.725 ;
     RECT  0.144 2.725 0.216 2.773 ;
     RECT  7.2 2.677 11.928 2.821 ;
     RECT  0.144 2.773 0.36 2.915 ;
     RECT  15.9 2.437 19.368 2.915 ;
     RECT  7.2 2.821 11.976 2.965 ;
     RECT  13.008 2.137 14.808 2.965 ;
     RECT  2.4 2.151 3.576 3.061 ;
     RECT  7.2 2.965 14.808 3.445 ;
     RECT  15.9 2.915 19.272 3.445 ;
     RECT  0.192 2.915 0.36 3.493 ;
     RECT  2.304 3.061 3.576 3.541 ;
     RECT  7.152 3.445 14.808 3.637 ;
     RECT  15.792 3.445 19.272 3.637 ;
     RECT  2.304 3.541 3.624 3.685 ;
     RECT  4.608 2.151 5.412 3.685 ;
     RECT  0.192 3.493 0.408 4.165 ;
     RECT  2.304 3.685 5.412 4.165 ;
     RECT  0.144 4.165 0.408 4.309 ;
     RECT  7.152 3.637 19.272 4.405 ;
     RECT  2.304 4.165 5.736 4.499 ;
     RECT  7.152 4.405 19.32 4.643 ;
     RECT  0.144 4.309 0.504 4.691 ;
     RECT  2.4 4.499 5.736 5.027 ;
     RECT  7.2 4.643 19.32 5.509 ;
     RECT  0.144 4.691 0.456 6.181 ;
     RECT  7.2 5.509 19.368 6.229 ;
     RECT  7.008 6.229 19.368 6.323 ;
     RECT  7.008 6.323 19.32 6.419 ;
     RECT  2.4 5.027 5.412 6.757 ;
     RECT  2.4 6.757 5.592 6.901 ;
     RECT  2.4 6.901 5.976 7.141 ;
     RECT  0.144 6.181 0.552 7.429 ;
     RECT  7.008 6.419 8.112 7.715 ;
     RECT  9.504 6.419 19.32 7.717 ;
     RECT  7.296 7.715 8.112 7.957 ;
     RECT  9.264 7.717 19.32 7.957 ;
     RECT  2.304 7.141 5.976 8.051 ;
     RECT  0.144 7.429 0.6 8.101 ;
     RECT  21.408 8.197 21.432 8.483 ;
     RECT  0.144 8.101 0.648 8.579 ;
     RECT  7.296 7.957 19.32 8.627 ;
     RECT  7.296 8.627 10.968 8.773 ;
     RECT  0.192 8.579 0.648 8.867 ;
     RECT  2.4 8.051 5.976 9.061 ;
     RECT  7.104 8.773 10.968 9.061 ;
     RECT  2.4 9.061 10.968 9.299 ;
     RECT  5.1 9.299 10.968 9.829 ;
     RECT  11.952 8.627 19.32 9.829 ;
     RECT  0.192 8.867 0.504 9.877 ;
     RECT  0.192 9.877 0.552 9.925 ;
     RECT  21.408 9.877 21.432 10.163 ;
     RECT  5.1 9.829 19.32 10.307 ;
     RECT  2.4 9.299 4.008 10.693 ;
     RECT  2.256 10.693 4.008 10.741 ;
     RECT  5.1 10.307 19.08 10.741 ;
     RECT  2.256 10.741 19.08 10.883 ;
     RECT  21.36 11.749 21.384 11.987 ;
     RECT  2.256 10.883 18.912 11.989 ;
     RECT  0.144 9.925 0.552 12.611 ;
     RECT  21.408 12.565 21.432 12.851 ;
     RECT  2.256 11.989 19.032 13.235 ;
     RECT  0.144 12.611 0.504 13.765 ;
     RECT  0.144 13.765 1.272 14.053 ;
     RECT  2.256 13.235 18.912 14.053 ;
     RECT  21.408 14.437 21.432 14.723 ;
     RECT  0.144 14.053 18.912 14.917 ;
     RECT  0.144 14.917 19.8 15.107 ;
     RECT  0.144 15.107 18.912 16.117 ;
     RECT  0.144 16.117 19.08 16.883 ;
     RECT  0.144 16.883 1.08 16.931 ;
     RECT  2.256 16.883 19.08 16.931 ;
     RECT  0.144 16.931 0.84 17.219 ;
     RECT  2.256 16.931 19.032 17.507 ;
     RECT  21.408 17.941 21.432 18.227 ;
     RECT  0.144 17.219 0.648 18.275 ;
     RECT  0.192 18.275 0.648 18.563 ;
     RECT  0.192 18.563 0.552 18.899 ;
     RECT  0.192 18.899 0.408 19.237 ;
     RECT  2.256 17.507 18.912 20.005 ;
     RECT  0.144 19.237 0.408 20.389 ;
     RECT  21.408 20.245 21.432 20.435 ;
     RECT  0.144 20.389 0.504 20.485 ;
     RECT  2.256 20.005 19.032 21.683 ;
     RECT  21.408 21.733 21.432 21.923 ;
     RECT  21.312 22.021 21.384 22.163 ;
     RECT  21.36 22.163 21.384 22.787 ;
     RECT  2.256 21.683 9.048 23.029 ;
     RECT  10.08 21.683 19.032 23.029 ;
     RECT  2.256 23.029 19.032 23.171 ;
     RECT  21.408 23.125 21.432 23.315 ;
     RECT  2.4 23.171 19.032 23.845 ;
     RECT  2.4 23.845 19.368 24.563 ;
     RECT  0.144 20.485 0.552 24.707 ;
     RECT  21.456 24.613 21.48 24.755 ;
     RECT  2.4 24.563 19.08 24.901 ;
     RECT  2.304 24.901 19.08 26.387 ;
     RECT  0.144 24.707 0.504 26.437 ;
     RECT  0.144 26.437 0.552 26.915 ;
     RECT  2.304 26.387 18.912 27.347 ;
     RECT  21.408 27.733 21.432 27.923 ;
     RECT  9.744 27.347 18.912 28.117 ;
     RECT  0.144 26.915 0.504 28.405 ;
     RECT  0.144 28.405 0.552 28.837 ;
     RECT  0.144 28.837 0.6 28.933 ;
     RECT  2.304 27.347 8.52 29.173 ;
     RECT  9.744 28.117 19.032 29.173 ;
     RECT  21.312 29.461 21.336 29.651 ;
     RECT  0.144 28.933 0.648 29.941 ;
     RECT  2.304 29.173 19.032 30.083 ;
     RECT  0.144 29.941 0.696 30.181 ;
     RECT  0.144 30.181 0.744 30.469 ;
     RECT  12.048 30.083 19.032 30.611 ;
     RECT  12.096 30.611 19.032 30.851 ;
     RECT  21.408 30.757 21.432 30.947 ;
     RECT  0.144 30.469 0.792 31.045 ;
     RECT  2.304 30.083 10.92 31.045 ;
     RECT  2.304 31.045 11.112 31.187 ;
     RECT  12.096 30.851 18.912 31.427 ;
     RECT  2.304 31.187 10.812 31.571 ;
     RECT  2.304 31.571 5.688 31.619 ;
     RECT  6.72 31.571 10.812 31.715 ;
     RECT  7.8 31.715 10.812 31.763 ;
     RECT  6.72 31.715 6.744 31.811 ;
     RECT  12.432 31.427 18.912 31.859 ;
     RECT  2.4 31.619 5.688 31.955 ;
     RECT  9.648 31.763 10.812 31.955 ;
     RECT  12.432 31.859 14.616 31.955 ;
     RECT  15.9 31.859 18.912 31.955 ;
     RECT  2.4 31.955 5.592 32.003 ;
     RECT  2.4 32.003 3.432 32.099 ;
     RECT  14.592 31.955 14.616 32.147 ;
     RECT  4.464 32.003 5.412 32.243 ;
     RECT  17.376 31.955 17.4 32.291 ;
     RECT  2.4 32.099 2.712 32.409 ;
     RECT  5.1 32.243 5.412 32.409 ;
     RECT  7.8 31.763 8.112 32.409 ;
     RECT  10.5 31.955 10.812 32.409 ;
     RECT  13.2 31.955 13.512 32.409 ;
     RECT  15.9 31.955 16.212 32.409 ;
     RECT  18.6 31.955 18.912 32.409 ;
     RECT  2.4 32.409 2.52 32.423 ;
     RECT  5.1 32.409 5.22 32.423 ;
     RECT  7.8 32.409 7.92 32.423 ;
     RECT  10.5 32.409 10.62 32.423 ;
     RECT  13.2 32.409 13.32 32.423 ;
     RECT  15.9 32.409 16.02 32.423 ;
     RECT  18.6 32.409 18.72 32.423 ;
     RECT  0.144 31.045 1.128 32.531 ;
     RECT  0.192 32.531 1.128 33.203 ;
     RECT  0.288 33.203 1.128 33.587 ;
     RECT  0.72 33.587 1.128 33.683 ;
     RECT  1.104 33.683 1.128 33.779 ;
  END
END hbfd_rly_304_WE_rrfc
END LIBRARY
